NAMESCASESENSITIVE ON ;

SITE IOSite
  CLASS       PAD ;
  SYMMETRY    X Y R90 ;
  SIZE        0.010 BY 80.000 ;
END IOSite

SITE CornerSite
  CLASS       PAD ;
  SYMMETRY    X Y R90 ;
  SIZE        80.000 BY 80.000 ;
END CornerSite

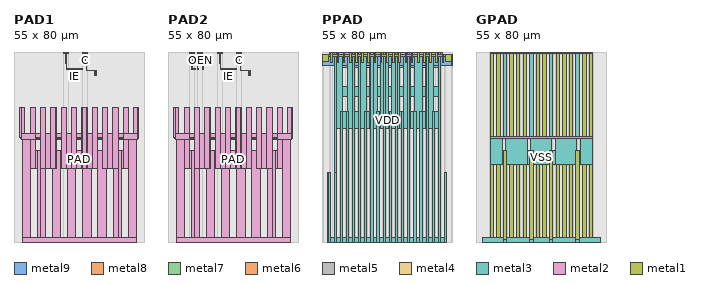
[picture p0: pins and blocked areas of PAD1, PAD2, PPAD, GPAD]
MACRO PAD1
  CLASS PAD ;
  ORIGIN 0 0 ;
  FOREIGN PAD1 0 0 ;
  SIZE 55 BY 80 ;
  SYMMETRY X Y R90 ;
  SITE IOSite ;
  PIN C
    DIRECTION OUTPUT ;
    USE SIGNAL ;
    PORT
      LAYER metal9 ;
        RECT 28.93 79.46 30.89 80 ;
      LAYER metal8 ;
        RECT 28.93 79.46 30.89 80 ;
      LAYER metal7 ;
        RECT 28.93 79.46 30.89 80 ;
      LAYER metal6 ;
        RECT 28.93 79.46 30.89 80 ;
      LAYER metal5 ;
        RECT 28.93 79.46 30.89 80 ;
      LAYER metal4 ;
        RECT 28.93 79.46 30.89 80 ;
      LAYER metal3 ;
        RECT 28.93 79.46 30.89 80 ;
      LAYER metal2 ;
        RECT 30.375 72.005 34.58 72.175 ;
        RECT 34.41 70.005 34.58 72.175 ;
        RECT 33.69 70.005 33.86 72.175 ;
        RECT 31.06 75.765 31.23 76.185 ;
        RECT 29.14 75.765 31.23 75.935 ;
        RECT 28.93 79.46 30.89 80 ;
        RECT 30.42 75.765 30.59 76.185 ;
        RECT 30.375 72.005 30.545 75.935 ;
        RECT 29.825 75.765 29.995 80 ;
        RECT 29.78 75.765 29.995 76.185 ;
        RECT 29.14 75.765 29.31 76.185 ;
      LAYER metal1 ;
        RECT 28.93 79.46 30.89 80 ;
    END
  AntennaGateArea 0.000 ;
  AntennaDiffArea 0.590 ;
  END C
  PIN IE
    DIRECTION INPUT ;
    USE SIGNAL ;
    PORT
      LAYER metal9 ;
        RECT 20.9 79.46 22.86 80 ;
      LAYER metal8 ;
        RECT 20.9 79.46 22.86 80 ;
      LAYER metal7 ;
        RECT 20.9 79.46 22.86 80 ;
      LAYER metal6 ;
        RECT 20.9 79.46 22.86 80 ;
      LAYER metal5 ;
        RECT 20.9 79.46 22.86 80 ;
      LAYER metal4 ;
        RECT 20.9 79.46 22.86 80 ;
      LAYER metal3 ;
        RECT 20.9 79.46 22.86 80 ;
      LAYER metal2 ;
        RECT 22.145 72.72 28.86 72.89 ;
        RECT 20.9 79.46 22.86 80 ;
        RECT 21.795 75.1 22.315 75.27 ;
        RECT 22.145 72.72 22.315 75.27 ;
        RECT 21.795 75.1 21.965 80 ;
      LAYER metal1 ;
        RECT 20.9 79.46 22.86 80 ;
    END
  AntennaGateArea 3.110 ;
  AntennaDiffArea 0.590 ;
  END IE
  PIN PAD
    DIRECTION INPUT ;
    USE SIGNAL ;
    PORT
      LAYER metal9 ;
        RECT 3.415 0 51.585 2 ;
      LAYER metal8 ;
        RECT 3.415 0 51.585 2 ;
      LAYER metal7 ;
        RECT 3.415 0 51.585 2 ;
      LAYER metal6 ;
        RECT 3.415 0 51.585 2 ;
      LAYER metal5 ;
        RECT 3.415 0 51.585 2 ;
      LAYER metal4 ;
        RECT 3.415 0 51.585 2 ;
      LAYER metal3 ;
        RECT 50.395 43.9 52.565 56.445 ;
        RECT 50.445 43.85 52.535 56.495 ;
        RECT 2.515 43.8 52.485 45.78 ;
        RECT 2.565 43.75 52.435 45.78 ;
        RECT 2.615 43.7 52.385 45.78 ;
        RECT 2.665 43.65 52.335 45.78 ;
        RECT 2.715 43.6 52.285 45.78 ;
        RECT 2.765 43.55 52.235 45.78 ;
        RECT 2.815 43.5 52.185 45.78 ;
        RECT 2.865 43.45 52.135 45.78 ;
        RECT 2.915 43.4 52.085 45.78 ;
        RECT 2.965 43.35 52.035 45.78 ;
        RECT 3.015 43.33 51.985 45.78 ;
        RECT 50.445 43.3 51.985 56.495 ;
        RECT 46.035 43.25 51.935 45.78 ;
        RECT 46.035 43.2 51.885 45.78 ;
        RECT 46.035 43.15 51.835 45.78 ;
        RECT 46.035 43.1 51.785 45.78 ;
        RECT 46.035 43.05 51.735 45.78 ;
        RECT 46.035 43 51.685 45.78 ;
        RECT 46.035 42.95 51.635 45.78 ;
        RECT 50.395 43.85 52.535 56.465 ;
        RECT 48.075 0 51.585 45.78 ;
        RECT 46.035 30.74 48.205 56.445 ;
        RECT 46.085 30.74 48.175 56.495 ;
        RECT 3.415 0 51.585 2 ;
        RECT 46.035 30.74 48.175 56.465 ;
        RECT 3.415 30.74 51.585 38.51 ;
        RECT 41.695 0 45.205 38.51 ;
        RECT 41.695 0 43.845 56.445 ;
        RECT 41.745 0 43.815 56.495 ;
        RECT 41.695 0 43.815 56.485 ;
        RECT 41.675 30.74 43.845 56.435 ;
        RECT 37.315 30.74 43.845 45.78 ;
        RECT 37.315 30.74 39.485 56.445 ;
        RECT 37.365 30.74 39.455 56.495 ;
        RECT 35.315 0 38.825 38.51 ;
        RECT 37.315 30.74 39.455 56.465 ;
        RECT 32.955 30.74 35.125 56.445 ;
        RECT 33.005 30.74 35.095 56.495 ;
        RECT 32.955 30.74 35.095 56.465 ;
        RECT 28.595 30.74 35.125 45.78 ;
        RECT 28.935 0 32.445 45.78 ;
        RECT 28.595 30.74 30.765 56.445 ;
        RECT 28.645 30.74 30.735 56.495 ;
        RECT 28.595 30.74 30.735 56.465 ;
        RECT 24.235 30.74 26.405 56.445 ;
        RECT 24.285 30.74 26.375 56.495 ;
        RECT 22.555 0 26.065 45.78 ;
        RECT 24.235 30.74 26.375 56.465 ;
        RECT 19.875 30.74 26.405 45.78 ;
        RECT 19.875 30.74 22.045 56.445 ;
        RECT 19.925 30.74 22.015 56.495 ;
        RECT 19.875 30.74 22.015 56.465 ;
        RECT 16.175 0 19.685 38.51 ;
        RECT 15.515 30.74 17.685 56.445 ;
        RECT 15.565 30.74 17.655 56.495 ;
        RECT 15.515 30.74 17.655 56.465 ;
        RECT 11.155 30.74 17.685 45.78 ;
        RECT 11.155 30.74 13.325 56.435 ;
        RECT 11.155 0 13.305 56.445 ;
        RECT 11.205 0 13.295 56.495 ;
        RECT 11.155 0 13.295 56.465 ;
        RECT 9.795 0 13.305 38.51 ;
        RECT 6.795 30.74 8.965 56.445 ;
        RECT 6.845 30.74 8.935 56.495 ;
        RECT 3.415 0 6.925 45.78 ;
        RECT 6.795 30.74 8.935 56.465 ;
        RECT 2.435 43.88 4.605 56.445 ;
        RECT 2.485 43.85 4.575 56.495 ;
        RECT 3.015 43.3 8.965 45.78 ;
        RECT 3.365 42.95 4.575 56.495 ;
        RECT 3.065 43.25 8.965 45.78 ;
        RECT 3.315 43 4.575 56.495 ;
        RECT 3.115 43.2 8.965 45.78 ;
        RECT 3.265 43.05 4.575 56.495 ;
        RECT 3.165 43.15 8.965 45.78 ;
        RECT 3.215 43.1 4.575 56.495 ;
        RECT 2.435 43.88 4.575 56.465 ;
      LAYER metal2 ;
        RECT 50.395 43.9 52.565 56.445 ;
        RECT 50.445 43.85 52.535 56.495 ;
        RECT 2.515 43.8 52.485 45.78 ;
        RECT 2.565 43.75 52.435 45.78 ;
        RECT 2.615 43.7 52.385 45.78 ;
        RECT 2.665 43.65 52.335 45.78 ;
        RECT 2.715 43.6 52.285 45.78 ;
        RECT 2.765 43.55 52.235 45.78 ;
        RECT 2.815 43.5 52.185 45.78 ;
        RECT 2.865 43.45 52.135 45.78 ;
        RECT 2.915 43.4 52.085 45.78 ;
        RECT 2.965 43.35 52.035 45.78 ;
        RECT 3.015 43.33 51.985 45.78 ;
        RECT 50.445 43.3 51.985 56.495 ;
        RECT 46.035 43.25 51.935 45.78 ;
        RECT 46.035 43.2 51.885 45.78 ;
        RECT 46.035 43.15 51.835 45.78 ;
        RECT 46.035 43.1 51.785 45.78 ;
        RECT 46.035 43.05 51.735 45.78 ;
        RECT 46.035 43 51.685 45.78 ;
        RECT 46.035 42.95 51.635 45.78 ;
        RECT 50.395 43.85 52.535 56.465 ;
        RECT 48.075 0 51.585 45.78 ;
        RECT 46.035 30.74 48.205 56.445 ;
        RECT 46.085 30.74 48.175 56.495 ;
        RECT 3.415 0 51.585 2 ;
        RECT 46.035 30.74 48.175 56.465 ;
        RECT 3.415 30.74 51.585 38.51 ;
        RECT 41.695 0 45.205 38.51 ;
        RECT 41.695 0 43.845 56.445 ;
        RECT 41.745 0 43.815 56.495 ;
        RECT 41.695 0 43.815 56.485 ;
        RECT 41.675 30.74 43.845 56.435 ;
        RECT 37.315 30.74 43.845 45.78 ;
        RECT 37.315 30.74 39.485 56.445 ;
        RECT 37.365 30.74 39.455 56.495 ;
        RECT 35.315 0 38.825 38.51 ;
        RECT 37.315 30.74 39.455 56.465 ;
        RECT 32.955 30.74 35.125 56.445 ;
        RECT 33.005 30.74 35.095 56.495 ;
        RECT 32.955 30.74 35.095 56.465 ;
        RECT 28.595 30.74 35.125 45.78 ;
        RECT 28.935 0 32.445 45.78 ;
        RECT 28.595 30.74 30.765 56.445 ;
        RECT 28.645 30.74 30.735 56.495 ;
        RECT 28.595 30.74 30.735 56.465 ;
        RECT 24.235 30.74 26.405 56.445 ;
        RECT 24.285 30.74 26.375 56.495 ;
        RECT 22.555 0 26.065 45.78 ;
        RECT 24.235 30.74 26.375 56.465 ;
        RECT 19.875 30.74 26.405 45.78 ;
        RECT 19.875 30.74 22.045 56.445 ;
        RECT 19.925 30.74 22.015 56.495 ;
        RECT 19.875 30.74 22.015 56.465 ;
        RECT 16.175 0 19.685 38.51 ;
        RECT 15.515 30.74 17.685 56.445 ;
        RECT 15.565 30.74 17.655 56.495 ;
        RECT 15.515 30.74 17.655 56.465 ;
        RECT 11.155 30.74 17.685 45.78 ;
        RECT 11.155 30.74 13.325 56.435 ;
        RECT 11.155 0 13.305 56.445 ;
        RECT 11.205 0 13.295 56.495 ;
        RECT 11.155 0 13.295 56.465 ;
        RECT 9.795 0 13.305 38.51 ;
        RECT 6.795 30.74 8.965 56.445 ;
        RECT 6.845 30.74 8.935 56.495 ;
        RECT 3.415 0 6.925 45.78 ;
        RECT 6.795 30.74 8.935 56.465 ;
        RECT 2.435 43.88 4.605 56.445 ;
        RECT 2.485 43.85 4.575 56.495 ;
        RECT 3.015 43.3 8.965 45.78 ;
        RECT 3.365 42.95 4.575 56.495 ;
        RECT 3.065 43.25 8.965 45.78 ;
        RECT 3.315 43 4.575 56.495 ;
        RECT 3.115 43.2 8.965 45.78 ;
        RECT 3.265 43.05 4.575 56.495 ;
        RECT 3.165 43.15 8.965 45.78 ;
        RECT 3.215 43.1 4.575 56.495 ;
        RECT 2.435 43.88 4.575 56.465 ;
    END
  END PAD
  OBS
    LAYER metal10 SPACING 0.4 ;
      RECT 0 0 55 80 ;
    LAYER via9 ;
      RECT 0 0 55 80 ;
    LAYER metal9 ;
      RECT 0 74.22 55 78.86 ;
      RECT 0 68.3 55 73.62 ;
      RECT 0 43.75 55 50.25 ;
      RECT 0 43.75 3 59.34 ;
      RECT 5.205 43.75 6.195 59.34 ;
      RECT 9.565 43.75 10.555 59.34 ;
      RECT 13.925 43.75 14.915 59.34 ;
      RECT 18.285 43.75 19.275 59.34 ;
      RECT 22.645 43.75 23.635 59.34 ;
      RECT 27.005 43.75 27.995 59.34 ;
      RECT 31.365 43.75 32.355 59.34 ;
      RECT 35.725 43.75 36.715 59.34 ;
      RECT 40.085 43.75 41.075 59.34 ;
      RECT 44.445 43.75 45.435 59.34 ;
      RECT 48.805 43.75 49.795 59.34 ;
      RECT 52 43.75 55 59.34 ;
      RECT 0 52.84 55 59.34 ;
      RECT 0 41.43 55 42.95 ;
      RECT 0 39.11 55 40.63 ;
      RECT 0 30.755 55 31.655 ;
      RECT 0 3.5 55 10.5 ;
      RECT 0 12.5 55 20.46 ;
      RECT 0 3.5 3 29.46 ;
      RECT 7.525 3.5 9.195 29.46 ;
      RECT 13.905 3.5 15.575 29.46 ;
      RECT 20.285 3.5 21.955 29.46 ;
      RECT 26.665 3.5 28.335 29.46 ;
      RECT 33.045 3.5 34.715 29.46 ;
      RECT 39.425 3.5 41.095 29.46 ;
      RECT 45.805 3.5 47.475 29.46 ;
      RECT 52 3.5 55 29.46 ;
      RECT 0 22.46 55 29.46 ;
    LAYER metal9 SPACING 0.4 ;
      RECT 0 0 2.785 80 ;
      RECT 0 2.63 55 78.86 ;
      RECT 0 2.63 20.27 80 ;
      RECT 23.49 2.63 28.3 80 ;
      RECT 52.215 0 55 80 ;
      RECT 31.52 2.63 55 80 ;
    LAYER via8 ;
      RECT 0 0 55 80 ;
    LAYER metal8 ;
      RECT 0 74.22 55 78.86 ;
      RECT 0 66.87 55 73.62 ;
      RECT 0 61.57 55 65.87 ;
      RECT 0 60.29 55 60.97 ;
      RECT 0 43.75 55 50.25 ;
      RECT 0 43.75 3 59.34 ;
      RECT 5.205 43.75 6.195 59.34 ;
      RECT 9.565 43.75 10.555 59.34 ;
      RECT 13.925 43.75 14.915 59.34 ;
      RECT 18.285 43.75 19.275 59.34 ;
      RECT 22.645 43.75 23.635 59.34 ;
      RECT 27.005 43.75 27.995 59.34 ;
      RECT 31.365 43.75 32.355 59.34 ;
      RECT 35.725 43.75 36.715 59.34 ;
      RECT 40.085 43.75 41.075 59.34 ;
      RECT 44.445 43.75 45.435 59.34 ;
      RECT 48.805 43.75 49.795 59.34 ;
      RECT 52 43.75 55 59.34 ;
      RECT 0 52.84 55 59.34 ;
      RECT 0 41.43 55 42.95 ;
      RECT 0 39.11 55 40.63 ;
      RECT 0 30.755 55 31.655 ;
      RECT 0 3.5 55 10.5 ;
      RECT 0 12.5 55 20.46 ;
      RECT 0 3.5 3 29.46 ;
      RECT 7.525 3.5 9.195 29.46 ;
      RECT 13.905 3.5 15.575 29.46 ;
      RECT 20.285 3.5 21.955 29.46 ;
      RECT 26.665 3.5 28.335 29.46 ;
      RECT 33.045 3.5 34.715 29.46 ;
      RECT 39.425 3.5 41.095 29.46 ;
      RECT 45.805 3.5 47.475 29.46 ;
      RECT 52 3.5 55 29.46 ;
      RECT 0 22.46 55 29.46 ;
    LAYER metal8 SPACING 0.1 ;
      RECT 0 0 3.085 80 ;
      RECT 0 2.33 55 79.13 ;
      RECT 0 2.33 20.57 80 ;
      RECT 23.19 2.33 28.6 80 ;
      RECT 51.915 0 55 80 ;
      RECT 31.22 2.33 55 80 ;
    LAYER via7 ;
      RECT 0 0 55 80 ;
    LAYER metal7 ;
      RECT 0 74.22 55 78.86 ;
      RECT 0 66.87 55 73.62 ;
      RECT 0 61.57 55 65.87 ;
      RECT 0 60.29 55 60.97 ;
      RECT 0 43.75 55 50.25 ;
      RECT 0 43.75 3 59.34 ;
      RECT 5.205 43.75 6.195 59.34 ;
      RECT 9.565 43.75 10.555 59.34 ;
      RECT 13.925 43.75 14.915 59.34 ;
      RECT 18.285 43.75 19.275 59.34 ;
      RECT 22.645 43.75 23.635 59.34 ;
      RECT 27.005 43.75 27.995 59.34 ;
      RECT 31.365 43.75 32.355 59.34 ;
      RECT 35.725 43.75 36.715 59.34 ;
      RECT 40.085 43.75 41.075 59.34 ;
      RECT 44.445 43.75 45.435 59.34 ;
      RECT 48.805 43.75 49.795 59.34 ;
      RECT 52 43.75 55 59.34 ;
      RECT 0 52.84 55 59.34 ;
      RECT 0 41.43 55 42.95 ;
      RECT 0 39.11 55 40.63 ;
      RECT 0 30.755 55 31.655 ;
      RECT 0 3.5 55 10.5 ;
      RECT 0 12.5 55 20.46 ;
      RECT 0 3.5 3 29.46 ;
      RECT 7.525 3.5 9.195 29.46 ;
      RECT 13.905 3.5 15.575 29.46 ;
      RECT 20.285 3.5 21.955 29.46 ;
      RECT 26.665 3.5 28.335 29.46 ;
      RECT 33.045 3.5 34.715 29.46 ;
      RECT 39.425 3.5 41.095 29.46 ;
      RECT 45.805 3.5 47.475 29.46 ;
      RECT 52 3.5 55 29.46 ;
      RECT 0 22.46 55 29.46 ;
    LAYER metal7 SPACING 0.1 ;
      RECT 0 0 3.24 80 ;
      RECT 0 2.175 55 79.285 ;
      RECT 0 2.175 20.725 80 ;
      RECT 23.035 2.175 28.755 80 ;
      RECT 51.76 0 55 80 ;
      RECT 31.065 2.175 55 80 ;
    LAYER via6 ;
      RECT 0 0 55 80 ;
    LAYER metal6 ;
      RECT 0 74.22 55 78.86 ;
      RECT 0 66.87 55 73.62 ;
      RECT 0 61.57 55 65.87 ;
      RECT 0 60.29 55 60.97 ;
      RECT 0 43.75 55 50.25 ;
      RECT 0 43.75 3 59.34 ;
      RECT 5.205 43.75 6.195 59.34 ;
      RECT 9.565 43.75 10.555 59.34 ;
      RECT 13.925 43.75 14.915 59.34 ;
      RECT 18.285 43.75 19.275 59.34 ;
      RECT 22.645 43.75 23.635 59.34 ;
      RECT 27.005 43.75 27.995 59.34 ;
      RECT 31.365 43.75 32.355 59.34 ;
      RECT 35.725 43.75 36.715 59.34 ;
      RECT 40.085 43.75 41.075 59.34 ;
      RECT 44.445 43.75 45.435 59.34 ;
      RECT 48.805 43.75 49.795 59.34 ;
      RECT 52 43.75 55 59.34 ;
      RECT 0 52.84 55 59.34 ;
      RECT 0 41.43 55 42.95 ;
      RECT 0 39.11 55 40.63 ;
      RECT 0 30.755 55 31.655 ;
      RECT 0 3.5 55 10.5 ;
      RECT 0 12.5 55 20.46 ;
      RECT 0 3.5 3 29.46 ;
      RECT 7.525 3.5 9.195 29.46 ;
      RECT 13.905 3.5 15.575 29.46 ;
      RECT 20.285 3.5 21.955 29.46 ;
      RECT 26.665 3.5 28.335 29.46 ;
      RECT 33.045 3.5 34.715 29.46 ;
      RECT 39.425 3.5 41.095 29.46 ;
      RECT 45.805 3.5 47.475 29.46 ;
      RECT 52 3.5 55 29.46 ;
      RECT 0 22.46 55 29.46 ;
    LAYER metal6 SPACING 0.1 ;
      RECT 0 0 3.24 80 ;
      RECT 0 2.175 55 79.285 ;
      RECT 0 2.175 20.725 80 ;
      RECT 23.035 2.175 28.755 80 ;
      RECT 51.76 0 55 80 ;
      RECT 31.065 2.175 55 80 ;
    LAYER via5 ;
      RECT 0 0 55 80 ;
    LAYER metal5 ;
      RECT 0 74.22 55 78.86 ;
      RECT 0 66.87 55 73.62 ;
      RECT 0 61.57 55 65.87 ;
      RECT 0 60.29 55 60.97 ;
      RECT 0 43.75 55 50.25 ;
      RECT 0 43.75 3 59.34 ;
      RECT 5.205 43.75 6.195 59.34 ;
      RECT 9.565 43.75 10.555 59.34 ;
      RECT 13.925 43.75 14.915 59.34 ;
      RECT 18.285 43.75 19.275 59.34 ;
      RECT 22.645 43.75 23.635 59.34 ;
      RECT 27.005 43.75 27.995 59.34 ;
      RECT 31.365 43.75 32.355 59.34 ;
      RECT 35.725 43.75 36.715 59.34 ;
      RECT 40.085 43.75 41.075 59.34 ;
      RECT 44.445 43.75 45.435 59.34 ;
      RECT 48.805 43.75 49.795 59.34 ;
      RECT 52 43.75 55 59.34 ;
      RECT 0 52.84 55 59.34 ;
      RECT 0 41.43 55 42.95 ;
      RECT 0 39.11 55 40.63 ;
      RECT 0 30.755 55 31.655 ;
      RECT 0 3.5 55 10.5 ;
      RECT 0 12.5 55 20.46 ;
      RECT 0 3.5 3 29.46 ;
      RECT 7.525 3.5 9.195 29.46 ;
      RECT 13.905 3.5 15.575 29.46 ;
      RECT 20.285 3.5 21.955 29.46 ;
      RECT 26.665 3.5 28.335 29.46 ;
      RECT 33.045 3.5 34.715 29.46 ;
      RECT 39.425 3.5 41.095 29.46 ;
      RECT 45.805 3.5 47.475 29.46 ;
      RECT 52 3.5 55 29.46 ;
      RECT 0 22.46 55 29.46 ;
    LAYER metal5 SPACING 0.1 ;
      RECT 0 0 3.24 80 ;
      RECT 0 2.175 55 79.285 ;
      RECT 0 2.175 20.725 80 ;
      RECT 23.035 2.175 28.755 80 ;
      RECT 51.76 0 55 80 ;
      RECT 31.065 2.175 55 80 ;
    LAYER via4 ;
      RECT 0 0 55 80 ;
    LAYER metal4 ;
      RECT 0 74.22 55 78.86 ;
      RECT 0 66.87 55 73.62 ;
      RECT 0 61.57 55 65.87 ;
      RECT 0 60.29 55 60.97 ;
      RECT 0 43.75 55 50.25 ;
      RECT 0 43.75 3 59.34 ;
      RECT 5.205 43.75 6.195 59.34 ;
      RECT 9.565 43.75 10.555 59.34 ;
      RECT 13.925 43.75 14.915 59.34 ;
      RECT 18.285 43.75 19.275 59.34 ;
      RECT 22.645 43.75 23.635 59.34 ;
      RECT 27.005 43.75 27.995 59.34 ;
      RECT 31.365 43.75 32.355 59.34 ;
      RECT 35.725 43.75 36.715 59.34 ;
      RECT 40.085 43.75 41.075 59.34 ;
      RECT 44.445 43.75 45.435 59.34 ;
      RECT 48.805 43.75 49.795 59.34 ;
      RECT 52 43.75 55 59.34 ;
      RECT 0 52.84 55 59.34 ;
      RECT 0 41.43 55 42.95 ;
      RECT 0 39.11 55 40.63 ;
      RECT 0 30.755 55 31.655 ;
      RECT 0 3.5 55 10.5 ;
      RECT 0 12.5 55 20.46 ;
      RECT 0 3.5 3 29.46 ;
      RECT 7.525 3.5 9.195 29.46 ;
      RECT 13.905 3.5 15.575 29.46 ;
      RECT 20.285 3.5 21.955 29.46 ;
      RECT 26.665 3.5 28.335 29.46 ;
      RECT 33.045 3.5 34.715 29.46 ;
      RECT 39.425 3.5 41.095 29.46 ;
      RECT 45.805 3.5 47.475 29.46 ;
      RECT 52 3.5 55 29.46 ;
      RECT 0 22.46 55 29.46 ;
    LAYER metal4 SPACING 0.1 ;
      RECT 0 0 3.24 80 ;
      RECT 0 2.175 55 79.285 ;
      RECT 0 2.175 20.725 80 ;
      RECT 23.035 2.175 28.755 80 ;
      RECT 51.76 0 55 80 ;
      RECT 31.065 2.175 55 80 ;
    LAYER via3 ;
      RECT 0 0 55 80 ;
    LAYER metal3 ;
      RECT 0 66.87 0.42 73.62 ;
      RECT 0 61.57 0.42 65.87 ;
      RECT 1.1 41.43 2.7 42.95 ;
      RECT 0 74.22 0.42 78.86 ;
      RECT 0 78.44 20.72 78.86 ;
      RECT 0.33 30.755 0.9 31.655 ;
      RECT 0.33 30.755 0.5 59.79 ;
      RECT 0.33 59.62 42.08 59.79 ;
      RECT 52.285 41.43 53.815 42.95 ;
      RECT 53.785 34.43 54.75 36.43 ;
      RECT 54.58 74.22 55 78.86 ;
      RECT 54.58 66.87 55 73.62 ;
      RECT 54.58 61.57 55 65.87 ;
    LAYER metal3 SPACING 0.1 ;
      RECT 7.1 2.175 9.62 30.565 ;
      RECT 9.14 38.685 10.98 43.155 ;
      RECT 13.48 2.175 16 30.565 ;
      RECT 17.86 38.685 19.7 43.155 ;
      RECT 19.86 2.175 22.38 30.565 ;
      RECT 26.58 38.685 28.42 43.155 ;
      RECT 26.24 2.175 28.76 30.565 ;
      RECT 32.62 2.175 35.14 30.565 ;
      RECT 35.3 38.685 37.14 43.155 ;
      RECT 39 2.175 41.52 30.565 ;
      RECT 44.02 38.685 45.86 43.155 ;
      RECT 45.38 2.175 47.9 30.565 ;
      RECT 0 0 3.24 42.775 ;
      RECT 51.76 0 55 42.775 ;
      RECT 0 0 3.19 42.825 ;
      RECT 51.81 0 55 42.825 ;
      RECT 0 0 3.14 42.875 ;
      RECT 51.86 0 55 42.875 ;
      RECT 0 0 3.09 42.925 ;
      RECT 51.91 0 55 42.925 ;
      RECT 0 0 3.04 42.975 ;
      RECT 51.96 0 55 42.975 ;
      RECT 0 0 2.99 43.025 ;
      RECT 52.01 0 55 43.025 ;
      RECT 0 0 2.94 43.075 ;
      RECT 52.06 0 55 43.075 ;
      RECT 0 0 2.89 43.125 ;
      RECT 52.11 0 55 43.125 ;
      RECT 0 0 2.84 43.175 ;
      RECT 52.16 0 55 43.175 ;
      RECT 0 0 2.79 43.225 ;
      RECT 52.21 0 55 43.225 ;
      RECT 0 0 2.74 43.275 ;
      RECT 52.26 0 55 43.275 ;
      RECT 0 0 2.69 43.325 ;
      RECT 52.31 0 55 43.325 ;
      RECT 0 0 2.64 43.375 ;
      RECT 52.36 0 55 43.375 ;
      RECT 0 0 2.59 43.425 ;
      RECT 52.41 0 55 43.425 ;
      RECT 0 0 2.54 43.475 ;
      RECT 52.46 0 55 43.475 ;
      RECT 0 0 2.49 43.525 ;
      RECT 52.51 0 55 43.525 ;
      RECT 0 0 2.44 43.575 ;
      RECT 52.56 0 55 43.575 ;
      RECT 0 0 2.39 43.625 ;
      RECT 52.61 0 55 43.625 ;
      RECT 0 0 2.34 43.675 ;
      RECT 52.66 0 55 43.675 ;
      RECT 0 0 2.31 43.705 ;
      RECT 52.71 0 55 43.725 ;
      RECT 39.66 45.955 41.5 80 ;
      RECT 13.48 56.61 15.34 80 ;
      RECT 22.22 45.955 24.06 79.285 ;
      RECT 0 0 2.26 80 ;
      RECT 4.78 45.955 6.62 80 ;
      RECT 4.75 56.62 6.62 80 ;
      RECT 9.14 45.955 10.98 80 ;
      RECT 9.11 56.62 10.98 80 ;
      RECT 13.5 45.955 15.34 80 ;
      RECT 13.47 56.62 15.34 80 ;
      RECT 17.86 45.955 19.7 80 ;
      RECT 17.83 56.62 19.7 80 ;
      RECT 22.19 56.62 24.06 79.285 ;
      RECT 26.58 45.955 28.42 80 ;
      RECT 26.55 56.62 28.42 80 ;
      RECT 30.91 56.62 32.78 79.285 ;
      RECT 35.3 45.955 37.14 80 ;
      RECT 35.27 56.62 37.14 80 ;
      RECT 44.02 45.955 45.86 80 ;
      RECT 43.99 56.62 45.86 80 ;
      RECT 48.38 45.955 50.22 80 ;
      RECT 48.35 56.62 50.22 80 ;
      RECT 39.66 56.61 41.52 80 ;
      RECT 39.63 56.62 41.52 80 ;
      RECT 0 56.64 2.31 80 ;
      RECT 4.75 56.64 6.67 80 ;
      RECT 9.11 56.64 11.03 80 ;
      RECT 13.47 56.64 15.39 80 ;
      RECT 17.83 56.64 19.75 80 ;
      RECT 22.19 56.64 24.11 79.285 ;
      RECT 26.55 56.64 28.47 80 ;
      RECT 30.91 56.64 32.83 79.285 ;
      RECT 35.27 56.64 37.19 80 ;
      RECT 39.63 56.66 41.57 80 ;
      RECT 43.99 56.64 45.91 80 ;
      RECT 48.35 56.64 50.27 80 ;
      RECT 52.71 56.62 55 80 ;
      RECT 30.94 45.955 32.78 79.285 ;
      RECT 0 56.67 55 79.285 ;
      RECT 0 56.67 20.725 80 ;
      RECT 23.035 56.67 28.755 80 ;
      RECT 52.74 0 55 80 ;
      RECT 31.065 56.67 55 80 ;
    LAYER via2 ;
      RECT 0 0 55 80 ;
    LAYER metal2 ;
      RECT 0 66.87 0.42 73.62 ;
      RECT 0 61.57 0.42 65.87 ;
      RECT 1.1 41.43 2.7 42.95 ;
      RECT 0 74.22 0.42 78.86 ;
      RECT 0 78.44 20.72 78.86 ;
      RECT 22.175 75.5 22.345 77.27 ;
      RECT 28.7 71.845 28.87 72.415 ;
      RECT 29.385 71.915 29.555 72.285 ;
      RECT 29.745 71.93 29.915 72.3 ;
      RECT 29.67 72.13 29.84 74.215 ;
      RECT 23.225 74.045 29.84 74.215 ;
      RECT 23.225 74.045 23.395 76.7 ;
      RECT 29.98 73.73 30.15 74.1 ;
      RECT 29.77 64.64 29.94 65.93 ;
      RECT 28.39 65.76 29.94 65.93 ;
      RECT 28.39 65.76 28.56 70.83 ;
      RECT 28.39 70.66 30.22 70.83 ;
      RECT 29.06 70.66 29.23 73.925 ;
      RECT 22.495 73.755 29.23 73.925 ;
      RECT 22.495 73.755 22.665 77.27 ;
      RECT 35.12 70.005 35.29 72.51 ;
      RECT 34.615 72.34 35.29 72.51 ;
      RECT 34.615 72.34 34.785 72.89 ;
      RECT 30.8 72.72 34.785 72.89 ;
      RECT 30.8 72.72 30.97 75.27 ;
      RECT 30.77 75.1 31.65 75.27 ;
      RECT 31.48 75.1 31.65 75.935 ;
      RECT 31.48 75.765 33.15 75.935 ;
      RECT 31.7 75.765 31.87 76.185 ;
      RECT 32.34 75.765 32.51 76.185 ;
      RECT 32.98 75.765 33.15 76.185 ;
      RECT 36.2 70.005 36.37 72.175 ;
      RECT 35.62 72.005 36.37 72.175 ;
      RECT 35.62 72.005 35.79 72.89 ;
      RECT 34.935 72.72 35.79 72.89 ;
      RECT 35.07 72.72 35.24 75.27 ;
      RECT 33.01 75.1 35.24 75.27 ;
      RECT 34.47 75.1 34.64 76.15 ;
      RECT 52.285 41.43 53.815 42.95 ;
      RECT 54.58 34.43 54.75 59.32 ;
      RECT 48.725 59.15 54.75 59.32 ;
      RECT 44.465 63.09 48.895 63.26 ;
      RECT 44.465 63.09 44.635 64.06 ;
      RECT 45.885 63.09 46.055 64.06 ;
      RECT 47.305 63.09 47.475 64.06 ;
      RECT 48.725 59.15 48.895 64.06 ;
      RECT 54.58 74.22 55 78.86 ;
      RECT 54.58 66.87 55 73.62 ;
      RECT 54.58 61.57 55 65.87 ;
    LAYER metal2 SPACING 0.1 ;
      RECT 7.1 2.175 9.62 30.565 ;
      RECT 9.14 38.685 10.98 43.155 ;
      RECT 13.48 2.175 16 30.565 ;
      RECT 17.86 38.685 19.7 43.155 ;
      RECT 19.86 2.175 22.38 30.565 ;
      RECT 26.58 38.685 28.42 43.155 ;
      RECT 26.24 2.175 28.76 30.565 ;
      RECT 32.62 2.175 35.14 30.565 ;
      RECT 35.3 38.685 37.14 43.155 ;
      RECT 39 2.175 41.52 30.565 ;
      RECT 44.02 38.685 45.86 43.155 ;
      RECT 45.38 2.175 47.9 30.565 ;
      RECT 0 0 3.24 42.775 ;
      RECT 51.76 0 55 42.775 ;
      RECT 0 0 3.19 42.825 ;
      RECT 51.81 0 55 42.825 ;
      RECT 0 0 3.14 42.875 ;
      RECT 51.86 0 55 42.875 ;
      RECT 0 0 3.09 42.925 ;
      RECT 51.91 0 55 42.925 ;
      RECT 0 0 3.04 42.975 ;
      RECT 51.96 0 55 42.975 ;
      RECT 0 0 2.99 43.025 ;
      RECT 52.01 0 55 43.025 ;
      RECT 0 0 2.94 43.075 ;
      RECT 52.06 0 55 43.075 ;
      RECT 0 0 2.89 43.125 ;
      RECT 52.11 0 55 43.125 ;
      RECT 0 0 2.84 43.175 ;
      RECT 52.16 0 55 43.175 ;
      RECT 0 0 2.79 43.225 ;
      RECT 52.21 0 55 43.225 ;
      RECT 0 0 2.74 43.275 ;
      RECT 52.26 0 55 43.275 ;
      RECT 0 0 2.69 43.325 ;
      RECT 52.31 0 55 43.325 ;
      RECT 0 0 2.64 43.375 ;
      RECT 52.36 0 55 43.375 ;
      RECT 0 0 2.59 43.425 ;
      RECT 52.41 0 55 43.425 ;
      RECT 0 0 2.54 43.475 ;
      RECT 52.46 0 55 43.475 ;
      RECT 0 0 2.49 43.525 ;
      RECT 52.51 0 55 43.525 ;
      RECT 0 0 2.44 43.575 ;
      RECT 52.56 0 55 43.575 ;
      RECT 0 0 2.39 43.625 ;
      RECT 52.61 0 55 43.625 ;
      RECT 0 0 2.34 43.675 ;
      RECT 52.66 0 55 43.675 ;
      RECT 0 0 2.31 43.705 ;
      RECT 52.71 0 55 43.725 ;
      RECT 39.66 45.955 41.5 80 ;
      RECT 13.48 56.61 15.34 80 ;
      RECT 0 0 2.26 80 ;
      RECT 4.78 45.955 6.62 80 ;
      RECT 4.75 56.62 6.62 80 ;
      RECT 9.14 45.955 10.98 80 ;
      RECT 9.11 56.62 10.98 80 ;
      RECT 13.5 45.955 15.34 80 ;
      RECT 13.47 56.62 15.34 80 ;
      RECT 17.86 45.955 19.7 80 ;
      RECT 17.83 56.62 19.7 80 ;
      RECT 22.22 45.955 24.06 72.545 ;
      RECT 22.19 56.62 24.06 72.545 ;
      RECT 26.58 45.955 28.42 72.545 ;
      RECT 26.55 56.62 28.42 72.545 ;
      RECT 30.94 45.955 32.78 71.83 ;
      RECT 30.91 56.62 32.78 71.83 ;
      RECT 35.3 45.955 37.14 80 ;
      RECT 35.27 56.62 37.14 80 ;
      RECT 44.02 45.955 45.86 80 ;
      RECT 43.99 56.62 45.86 80 ;
      RECT 48.38 45.955 50.22 80 ;
      RECT 48.35 56.62 50.22 80 ;
      RECT 39.66 56.61 41.52 80 ;
      RECT 39.63 56.62 41.52 80 ;
      RECT 0 56.64 2.31 80 ;
      RECT 4.75 56.64 6.67 80 ;
      RECT 9.11 56.64 11.03 80 ;
      RECT 13.47 56.64 15.39 80 ;
      RECT 17.83 56.64 19.75 80 ;
      RECT 22.19 56.64 24.11 72.545 ;
      RECT 26.55 56.64 28.47 72.545 ;
      RECT 30.91 56.64 32.83 71.83 ;
      RECT 35.27 56.64 37.19 80 ;
      RECT 39.63 56.66 41.57 80 ;
      RECT 43.99 56.64 45.91 80 ;
      RECT 48.35 56.64 50.27 80 ;
      RECT 0 56.67 55 69.83 ;
      RECT 0 56.67 33.515 71.83 ;
      RECT 34.035 56.67 34.235 71.83 ;
      RECT 34.755 56.67 55 80 ;
      RECT 34.615 72.34 55 80 ;
      RECT 0 56.67 30.2 72.545 ;
      RECT 0 56.67 21.97 74.925 ;
      RECT 22.49 73.065 30.2 75.59 ;
      RECT 29.035 56.67 30.2 75.59 ;
      RECT 30.72 72.35 55 75.59 ;
      RECT 22.14 75.445 28.965 79.285 ;
      RECT 29.485 76.11 29.605 79.285 ;
      RECT 30.765 76.11 30.885 79.285 ;
      RECT 52.71 56.62 55 80 ;
      RECT 31.405 72.35 55 80 ;
      RECT 0 56.67 21.62 79.285 ;
      RECT 22.14 76.36 29.65 79.285 ;
      RECT 30.17 76.36 55 79.285 ;
      RECT 0 56.67 20.725 80 ;
      RECT 23.035 73.065 28.755 80 ;
      RECT 52.74 0 55 80 ;
      RECT 31.065 76.36 55 80 ;
    LAYER via1 ;
      RECT 0 0 55 80 ;
    LAYER metal1 ;
      RECT 0 74.22 55 74.64 ;
      RECT 24.315 74.22 24.715 75.02 ;
      RECT 25.475 74.22 25.875 75.02 ;
      RECT 26.635 74.22 27.035 75.02 ;
      RECT 44.935 74.22 45.335 75.02 ;
      RECT 46.095 74.22 46.495 75.02 ;
      RECT 47.255 74.22 47.655 75.02 ;
      RECT 48.415 74.22 48.815 75.02 ;
      RECT 49.575 74.22 49.975 75.02 ;
      RECT 50.735 74.22 51.135 75.02 ;
      RECT 51.895 74.22 52.295 75.02 ;
      RECT 53.055 74.22 53.455 75.02 ;
      RECT 1.115 74.22 1.515 75.04 ;
      RECT 2.275 74.22 2.675 75.04 ;
      RECT 3.435 74.22 3.835 75.04 ;
      RECT 4.595 74.22 4.995 75.04 ;
      RECT 5.755 74.22 6.155 75.04 ;
      RECT 6.915 74.22 7.315 75.04 ;
      RECT 8.075 74.22 8.475 75.04 ;
      RECT 9.235 74.22 9.635 75.04 ;
      RECT 10.395 74.22 10.795 75.04 ;
      RECT 11.555 74.22 11.955 75.04 ;
      RECT 12.715 74.22 13.115 75.04 ;
      RECT 13.875 74.22 14.275 75.04 ;
      RECT 15.035 74.22 15.435 75.04 ;
      RECT 16.195 74.22 16.595 75.04 ;
      RECT 17.355 74.22 17.755 75.04 ;
      RECT 18.515 74.22 18.915 75.04 ;
      RECT 19.675 74.22 20.075 75.04 ;
      RECT 42.19 75.73 42.36 77.05 ;
      RECT 0 74.22 0.42 78.86 ;
      RECT 1.115 78.04 1.515 78.86 ;
      RECT 2.275 78.04 2.675 78.86 ;
      RECT 3.435 78.04 3.835 78.86 ;
      RECT 4.595 78.04 4.995 78.86 ;
      RECT 5.755 78.04 6.155 78.86 ;
      RECT 6.915 78.04 7.315 78.86 ;
      RECT 8.075 78.04 8.475 78.86 ;
      RECT 9.235 78.04 9.635 78.86 ;
      RECT 10.395 78.04 10.795 78.86 ;
      RECT 11.555 78.04 11.955 78.86 ;
      RECT 12.715 78.04 13.115 78.86 ;
      RECT 13.875 78.04 14.275 78.86 ;
      RECT 15.035 78.04 15.435 78.86 ;
      RECT 16.195 78.04 16.595 78.86 ;
      RECT 17.355 78.04 17.755 78.86 ;
      RECT 18.515 78.04 18.915 78.86 ;
      RECT 19.675 78.04 20.075 78.86 ;
      RECT 20.92 74.22 21.42 78.86 ;
      RECT 22.175 75.5 22.345 78.86 ;
      RECT 22.905 75.73 23.075 78.86 ;
      RECT 24.315 78.02 24.715 78.86 ;
      RECT 25.475 78.02 25.875 78.86 ;
      RECT 26.635 78.02 27.035 78.86 ;
      RECT 27.855 74.22 28.355 78.86 ;
      RECT 28.82 75.73 28.99 78.86 ;
      RECT 29.46 75.73 29.63 78.86 ;
      RECT 30.1 75.73 30.27 78.86 ;
      RECT 30.74 75.73 30.91 78.86 ;
      RECT 31.38 75.73 31.55 78.86 ;
      RECT 32.02 75.73 32.19 78.86 ;
      RECT 32.66 75.73 32.83 78.86 ;
      RECT 33.3 75.73 33.47 78.86 ;
      RECT 34.15 75.71 34.32 78.86 ;
      RECT 34.79 75.71 34.96 78.86 ;
      RECT 36.615 75.635 36.785 78.86 ;
      RECT 38.035 75.635 38.205 78.86 ;
      RECT 39.455 75.635 39.625 78.86 ;
      RECT 40.77 75.73 40.94 78.86 ;
      RECT 42.23 75.915 42.4 78.86 ;
      RECT 43.685 74.22 43.935 78.86 ;
      RECT 44.935 78.02 45.335 78.86 ;
      RECT 46.095 78.02 46.495 78.86 ;
      RECT 47.255 78.02 47.655 78.86 ;
      RECT 48.415 78.02 48.815 78.86 ;
      RECT 49.575 78.02 49.975 78.86 ;
      RECT 50.735 78.02 51.135 78.86 ;
      RECT 51.895 78.02 52.295 78.86 ;
      RECT 53.055 78.02 53.455 78.86 ;
      RECT 54.58 74.22 55 78.86 ;
      RECT 0 78.44 55 78.86 ;
      RECT 0 66.87 55 67.29 ;
      RECT 1.115 66.87 1.515 67.775 ;
      RECT 2.275 66.87 2.675 67.775 ;
      RECT 3.435 66.87 3.835 67.775 ;
      RECT 4.595 66.87 4.995 67.775 ;
      RECT 5.755 66.87 6.155 67.775 ;
      RECT 6.915 66.87 7.315 67.775 ;
      RECT 8.075 66.87 8.475 67.775 ;
      RECT 9.235 66.87 9.635 67.775 ;
      RECT 10.395 66.87 10.795 67.775 ;
      RECT 11.555 66.87 11.955 67.775 ;
      RECT 12.715 66.87 13.115 67.775 ;
      RECT 13.875 66.87 14.275 67.775 ;
      RECT 15.035 66.87 15.435 67.775 ;
      RECT 16.195 66.87 16.595 67.775 ;
      RECT 17.355 66.87 17.755 67.775 ;
      RECT 18.515 66.87 18.915 67.775 ;
      RECT 19.675 66.87 20.075 67.775 ;
      RECT 20.835 66.87 21.235 67.775 ;
      RECT 21.995 66.87 22.395 67.775 ;
      RECT 23.155 66.87 23.555 67.775 ;
      RECT 24.315 66.87 24.715 67.775 ;
      RECT 25.475 66.87 25.875 67.775 ;
      RECT 28.7 66.87 28.87 70.295 ;
      RECT 30.4 66.87 30.57 70.295 ;
      RECT 32.1 66.87 32.27 70.295 ;
      RECT 27.14 66.87 27.31 71.385 ;
      RECT 33.33 66.87 33.5 72.295 ;
      RECT 34.05 66.87 34.22 72.295 ;
      RECT 34.76 66.87 34.93 72.295 ;
      RECT 35.84 66.87 36.01 72.295 ;
      RECT 36.56 66.87 36.73 72.295 ;
      RECT 0 66.87 0.42 73.62 ;
      RECT 1.115 72.85 1.515 73.62 ;
      RECT 2.275 72.85 2.675 73.62 ;
      RECT 3.435 72.85 3.835 73.62 ;
      RECT 4.595 72.85 4.995 73.62 ;
      RECT 5.755 72.85 6.155 73.62 ;
      RECT 6.915 72.85 7.315 73.62 ;
      RECT 8.075 72.85 8.475 73.62 ;
      RECT 9.235 72.85 9.635 73.62 ;
      RECT 10.395 72.85 10.795 73.62 ;
      RECT 11.555 72.85 11.955 73.62 ;
      RECT 12.715 72.85 13.115 73.62 ;
      RECT 13.875 72.85 14.275 73.62 ;
      RECT 15.035 72.85 15.435 73.62 ;
      RECT 16.195 72.85 16.595 73.62 ;
      RECT 17.355 72.85 17.755 73.62 ;
      RECT 18.515 72.85 18.915 73.62 ;
      RECT 19.675 72.85 20.075 73.62 ;
      RECT 20.835 72.85 21.235 73.62 ;
      RECT 21.995 72.85 22.395 73.62 ;
      RECT 23.155 72.85 23.555 73.62 ;
      RECT 24.315 72.85 24.715 73.62 ;
      RECT 25.475 72.85 25.875 73.62 ;
      RECT 52.44 71.34 52.61 73.62 ;
      RECT 54.695 66.87 55 73.62 ;
      RECT 0 73.2 55 73.62 ;
      RECT 0 61.57 55 61.99 ;
      RECT 1.115 61.57 1.515 62.34 ;
      RECT 2.275 61.57 2.675 62.34 ;
      RECT 3.435 61.57 3.835 62.34 ;
      RECT 4.595 61.57 4.995 62.34 ;
      RECT 5.755 61.57 6.155 62.34 ;
      RECT 6.915 61.57 7.315 62.34 ;
      RECT 8.075 61.57 8.475 62.34 ;
      RECT 9.235 61.57 9.635 62.34 ;
      RECT 10.395 61.57 10.795 62.34 ;
      RECT 11.555 61.57 11.955 62.34 ;
      RECT 12.715 61.57 13.115 62.34 ;
      RECT 13.875 61.57 14.275 62.34 ;
      RECT 15.035 61.57 15.435 62.34 ;
      RECT 16.195 61.57 16.595 62.34 ;
      RECT 17.355 61.57 17.755 62.34 ;
      RECT 18.515 61.57 18.915 62.34 ;
      RECT 19.675 61.57 20.075 62.34 ;
      RECT 20.835 61.57 21.235 62.34 ;
      RECT 21.995 61.57 22.395 62.34 ;
      RECT 23.155 61.57 23.555 62.34 ;
      RECT 24.315 61.57 24.715 62.34 ;
      RECT 25.475 61.57 25.875 62.34 ;
      RECT 30.835 61.57 31.005 64.22 ;
      RECT 36.545 61.57 36.715 64.41 ;
      RECT 50.73 61.57 50.9 64.41 ;
      RECT 52.15 61.57 52.32 64.41 ;
      RECT 37.665 61.57 37.835 64.43 ;
      RECT 39.085 61.57 39.255 64.43 ;
      RECT 40.505 61.57 40.675 64.505 ;
      RECT 0 61.57 0.42 65.87 ;
      RECT 1.115 65.1 1.515 65.87 ;
      RECT 2.275 65.1 2.675 65.87 ;
      RECT 3.435 65.1 3.835 65.87 ;
      RECT 4.595 65.1 4.995 65.87 ;
      RECT 5.755 65.1 6.155 65.87 ;
      RECT 6.915 65.1 7.315 65.87 ;
      RECT 8.075 65.1 8.475 65.87 ;
      RECT 9.235 65.1 9.635 65.87 ;
      RECT 10.395 65.1 10.795 65.87 ;
      RECT 11.555 65.1 11.955 65.87 ;
      RECT 12.715 65.1 13.115 65.87 ;
      RECT 13.875 65.1 14.275 65.87 ;
      RECT 15.035 65.1 15.435 65.87 ;
      RECT 16.195 65.1 16.595 65.87 ;
      RECT 17.355 65.1 17.755 65.87 ;
      RECT 18.515 65.1 18.915 65.87 ;
      RECT 19.675 65.1 20.075 65.87 ;
      RECT 20.835 65.1 21.235 65.87 ;
      RECT 21.995 65.1 22.395 65.87 ;
      RECT 23.155 65.1 23.555 65.87 ;
      RECT 24.315 65.1 24.715 65.87 ;
      RECT 25.475 65.1 25.875 65.87 ;
      RECT 26.92 61.57 27.42 65.87 ;
      RECT 28.29 64.04 28.46 65.87 ;
      RECT 54.58 61.57 55 65.87 ;
      RECT 0 65.45 55 65.87 ;
      RECT 0 60.29 55 60.97 ;
      RECT 0 43.75 55 45.065 ;
      RECT 0 46.53 1.835 56.445 ;
      RECT 53.165 46.51 55 56.465 ;
      RECT 0 46.48 1.805 56.495 ;
      RECT 53.215 46.48 55 56.495 ;
      RECT 0 43.75 0.5 59.34 ;
      RECT 54.5 43.75 55 59.34 ;
      RECT 0 57.97 55 59.34 ;
      RECT 0 41.43 55 42.95 ;
      RECT 0 39.11 55 40.63 ;
      RECT 0 0 55 0.4 ;
      RECT 0 3.85 2.815 27.95 ;
      RECT 52.185 3.85 55 27.95 ;
      RECT 0 3.8 2.765 28 ;
      RECT 52.235 3.8 55 28 ;
      RECT 0 3.75 2.715 28.05 ;
      RECT 52.285 3.75 55 28.05 ;
      RECT 0 3.7 2.665 28.1 ;
      RECT 52.335 3.7 55 28.1 ;
      RECT 0 3.65 2.615 28.15 ;
      RECT 52.385 3.65 55 28.15 ;
      RECT 0 3.6 2.565 28.2 ;
      RECT 52.435 3.6 55 28.2 ;
      RECT 0 0 1.185 33.47 ;
      RECT 53.815 0 55 32.93 ;
      RECT 0 32.55 55 32.93 ;
      RECT 0 32.55 40.715 33.47 ;
      RECT 0 0 0.75 38.31 ;
      RECT 2.025 35.53 40.715 38.31 ;
      RECT 6.15 32.55 40.715 38.31 ;
      RECT 0 36.04 40.715 38.31 ;
      RECT 54.6 0 55 38.31 ;
      RECT 0 37.93 55 38.31 ;
    LAYER metal1 SPACING 0.09 ;
      RECT 0 0 55 79.295 ;
      RECT 0 0 20.735 80 ;
      RECT 23.025 0 28.765 80 ;
      RECT 31.055 0 55 80 ;
  END
END PAD1
MACRO PAD2
  CLASS PAD ;
  ORIGIN 0 0 ;
  FOREIGN PAD2 0 0 ;
  SIZE 55 BY 80 ;
  SYMMETRY X Y R90 ;
  SITE IOSite ;
  PIN C
    DIRECTION OUTPUT ;
    USE SIGNAL ;
    PORT
      LAYER metal9 ;
        RECT 28.93 79.46 30.89 80 ;
      LAYER metal8 ;
        RECT 28.93 79.46 30.89 80 ;
      LAYER metal7 ;
        RECT 28.93 79.46 30.89 80 ;
      LAYER metal6 ;
        RECT 28.93 79.46 30.89 80 ;
      LAYER metal5 ;
        RECT 28.93 79.46 30.89 80 ;
      LAYER metal4 ;
        RECT 28.93 79.46 30.89 80 ;
      LAYER metal3 ;
        RECT 28.93 79.46 30.89 80 ;
      LAYER metal2 ;
        RECT 30.375 72.005 34.58 72.175 ;
        RECT 34.41 70.005 34.58 72.175 ;
        RECT 33.69 70.005 33.86 72.175 ;
        RECT 31.06 75.765 31.23 76.185 ;
        RECT 29.14 75.765 31.23 75.935 ;
        RECT 28.93 79.46 30.89 80 ;
        RECT 30.42 75.765 30.59 76.185 ;
        RECT 30.375 72.005 30.545 75.935 ;
        RECT 29.825 75.765 29.995 80 ;
        RECT 29.78 75.765 29.995 76.185 ;
        RECT 29.14 75.765 29.31 76.185 ;
      LAYER metal1 ;
        RECT 28.93 79.46 30.89 80 ;
    END
  AntennaGateArea 0.000 ;
  AntennaDiffArea 0.590 ;
  END C
  PIN I
    DIRECTION INPUT ;
    USE SIGNAL ;
    PORT
      LAYER metal9 ;
        RECT 9.105 79.46 11.065 80 ;
      LAYER metal8 ;
        RECT 9.105 79.46 11.065 80 ;
      LAYER metal7 ;
        RECT 9.105 79.46 11.065 80 ;
      LAYER metal6 ;
        RECT 9.105 79.46 11.065 80 ;
      LAYER metal5 ;
        RECT 9.105 79.46 11.065 80 ;
      LAYER metal4 ;
        RECT 9.105 79.46 11.065 80 ;
      LAYER metal3 ;
        RECT 10 75.1 15.445 75.27 ;
        RECT 10 72.72 11.53 72.89 ;
        RECT 9.105 79.46 11.065 80 ;
        RECT 10 72.72 10.17 80 ;
      LAYER metal2 ;
        RECT 9.105 79.46 11.065 80 ;
      LAYER metal1 ;
        RECT 9.105 79.46 11.065 80 ;
    END
  AntennaGateArea 0.700 ;
  AntennaDiffArea 0.590 ;
  END I
  PIN IE
    DIRECTION INPUT ;
    USE SIGNAL ;
    PORT
      LAYER metal9 ;
        RECT 20.9 79.46 22.86 80 ;
      LAYER metal8 ;
        RECT 20.9 79.46 22.86 80 ;
      LAYER metal7 ;
        RECT 20.9 79.46 22.86 80 ;
      LAYER metal6 ;
        RECT 20.9 79.46 22.86 80 ;
      LAYER metal5 ;
        RECT 20.9 79.46 22.86 80 ;
      LAYER metal4 ;
        RECT 20.9 79.46 22.86 80 ;
      LAYER metal3 ;
        RECT 20.9 79.46 22.86 80 ;
      LAYER metal2 ;
        RECT 22.145 72.72 28.86 72.89 ;
        RECT 20.9 79.46 22.86 80 ;
        RECT 21.795 75.1 22.315 75.27 ;
        RECT 22.145 72.72 22.315 75.27 ;
        RECT 21.795 75.1 21.965 80 ;
      LAYER metal1 ;
        RECT 20.9 79.46 22.86 80 ;
    END
  AntennaGateArea 3.110 ;
  AntennaDiffArea 0.590 ;
  END IE
  PIN OEN
    DIRECTION INPUT ;
    USE SIGNAL ;
    PORT
      LAYER metal9 ;
        RECT 12.495 79.46 14.455 80 ;
      LAYER metal8 ;
        RECT 12.495 79.46 14.455 80 ;
      LAYER metal7 ;
        RECT 12.495 79.46 14.455 80 ;
      LAYER metal6 ;
        RECT 12.495 79.46 14.455 80 ;
      LAYER metal5 ;
        RECT 12.495 79.46 14.455 80 ;
      LAYER metal4 ;
        RECT 12.495 79.46 14.455 80 ;
      LAYER metal3 ;
        RECT 12.495 79.46 14.455 80 ;
      LAYER metal2 ;
        RECT 12.43 75.1 14.835 75.27 ;
        RECT 14.625 72.72 14.795 75.27 ;
        RECT 14.425 72.72 14.795 72.89 ;
        RECT 12.495 79.46 14.455 80 ;
        RECT 13.39 75.1 13.56 80 ;
        RECT 12.43 72.72 12.8 72.89 ;
        RECT 12.43 72.72 12.6 75.27 ;
      LAYER metal1 ;
        RECT 12.495 79.46 14.455 80 ;
    END
  AntennaGateArea 0.560 ;
  AntennaDiffArea 0.590 ;
  END OEN
  PIN PAD
    DIRECTION INOUT ;
    USE SIGNAL ;
    PORT
      LAYER metal9 ;
        RECT 3.415 0 51.585 2 ;
      LAYER metal8 ;
        RECT 3.415 0 51.585 2 ;
      LAYER metal7 ;
        RECT 3.415 0 51.585 2 ;
      LAYER metal6 ;
        RECT 3.415 0 51.585 2 ;
      LAYER metal5 ;
        RECT 3.415 0 51.585 2 ;
      LAYER metal4 ;
        RECT 3.415 0 51.585 2 ;
      LAYER metal3 ;
        RECT 50.395 43.9 52.565 56.445 ;
        RECT 50.445 43.85 52.535 56.495 ;
        RECT 2.515 43.8 52.485 45.78 ;
        RECT 2.565 43.75 52.435 45.78 ;
        RECT 2.615 43.7 52.385 45.78 ;
        RECT 2.665 43.65 52.335 45.78 ;
        RECT 2.715 43.6 52.285 45.78 ;
        RECT 2.765 43.55 52.235 45.78 ;
        RECT 2.815 43.5 52.185 45.78 ;
        RECT 2.865 43.45 52.135 45.78 ;
        RECT 2.915 43.4 52.085 45.78 ;
        RECT 2.965 43.35 52.035 45.78 ;
        RECT 3.015 43.33 51.985 45.78 ;
        RECT 50.445 43.3 51.985 56.495 ;
        RECT 46.035 43.25 51.935 45.78 ;
        RECT 46.035 43.2 51.885 45.78 ;
        RECT 46.035 43.15 51.835 45.78 ;
        RECT 46.035 43.1 51.785 45.78 ;
        RECT 46.035 43.05 51.735 45.78 ;
        RECT 46.035 43 51.685 45.78 ;
        RECT 46.035 42.95 51.635 45.78 ;
        RECT 50.395 43.85 52.535 56.465 ;
        RECT 48.075 0 51.585 45.78 ;
        RECT 46.035 30.74 48.205 56.445 ;
        RECT 46.085 30.74 48.175 56.495 ;
        RECT 3.415 0 51.585 2 ;
        RECT 46.035 30.74 48.175 56.465 ;
        RECT 3.415 30.74 51.585 38.51 ;
        RECT 41.695 0 45.205 38.51 ;
        RECT 41.695 0 43.845 56.445 ;
        RECT 41.745 0 43.815 56.495 ;
        RECT 41.695 0 43.815 56.485 ;
        RECT 41.675 30.74 43.845 56.435 ;
        RECT 37.315 30.74 43.845 45.78 ;
        RECT 37.315 30.74 39.485 56.445 ;
        RECT 37.365 30.74 39.455 56.495 ;
        RECT 35.315 0 38.825 38.51 ;
        RECT 37.315 30.74 39.455 56.465 ;
        RECT 32.955 30.74 35.125 56.445 ;
        RECT 33.005 30.74 35.095 56.495 ;
        RECT 32.955 30.74 35.095 56.465 ;
        RECT 28.595 30.74 35.125 45.78 ;
        RECT 28.935 0 32.445 45.78 ;
        RECT 28.595 30.74 30.765 56.445 ;
        RECT 28.645 30.74 30.735 56.495 ;
        RECT 28.595 30.74 30.735 56.465 ;
        RECT 24.235 30.74 26.405 56.445 ;
        RECT 24.285 30.74 26.375 56.495 ;
        RECT 22.555 0 26.065 45.78 ;
        RECT 24.235 30.74 26.375 56.465 ;
        RECT 19.875 30.74 26.405 45.78 ;
        RECT 19.875 30.74 22.045 56.445 ;
        RECT 19.925 30.74 22.015 56.495 ;
        RECT 19.875 30.74 22.015 56.465 ;
        RECT 16.175 0 19.685 38.51 ;
        RECT 15.515 30.74 17.685 56.445 ;
        RECT 15.565 30.74 17.655 56.495 ;
        RECT 15.515 30.74 17.655 56.465 ;
        RECT 11.155 30.74 17.685 45.78 ;
        RECT 11.155 30.74 13.325 56.435 ;
        RECT 11.155 0 13.305 56.445 ;
        RECT 11.205 0 13.295 56.495 ;
        RECT 11.155 0 13.295 56.465 ;
        RECT 9.795 0 13.305 38.51 ;
        RECT 6.795 30.74 8.965 56.445 ;
        RECT 6.845 30.74 8.935 56.495 ;
        RECT 3.415 0 6.925 45.78 ;
        RECT 6.795 30.74 8.935 56.465 ;
        RECT 2.435 43.88 4.605 56.445 ;
        RECT 2.485 43.85 4.575 56.495 ;
        RECT 3.015 43.3 8.965 45.78 ;
        RECT 3.365 42.95 4.575 56.495 ;
        RECT 3.065 43.25 8.965 45.78 ;
        RECT 3.315 43 4.575 56.495 ;
        RECT 3.115 43.2 8.965 45.78 ;
        RECT 3.265 43.05 4.575 56.495 ;
        RECT 3.165 43.15 8.965 45.78 ;
        RECT 3.215 43.1 4.575 56.495 ;
        RECT 2.435 43.88 4.575 56.465 ;
      LAYER metal2 ;
        RECT 50.395 43.9 52.565 56.445 ;
        RECT 50.445 43.85 52.535 56.495 ;
        RECT 2.515 43.8 52.485 45.78 ;
        RECT 2.565 43.75 52.435 45.78 ;
        RECT 2.615 43.7 52.385 45.78 ;
        RECT 2.665 43.65 52.335 45.78 ;
        RECT 2.715 43.6 52.285 45.78 ;
        RECT 2.765 43.55 52.235 45.78 ;
        RECT 2.815 43.5 52.185 45.78 ;
        RECT 2.865 43.45 52.135 45.78 ;
        RECT 2.915 43.4 52.085 45.78 ;
        RECT 2.965 43.35 52.035 45.78 ;
        RECT 3.015 43.33 51.985 45.78 ;
        RECT 50.445 43.3 51.985 56.495 ;
        RECT 46.035 43.25 51.935 45.78 ;
        RECT 46.035 43.2 51.885 45.78 ;
        RECT 46.035 43.15 51.835 45.78 ;
        RECT 46.035 43.1 51.785 45.78 ;
        RECT 46.035 43.05 51.735 45.78 ;
        RECT 46.035 43 51.685 45.78 ;
        RECT 46.035 42.95 51.635 45.78 ;
        RECT 50.395 43.85 52.535 56.465 ;
        RECT 48.075 0 51.585 45.78 ;
        RECT 46.035 30.74 48.205 56.445 ;
        RECT 46.085 30.74 48.175 56.495 ;
        RECT 3.415 0 51.585 2 ;
        RECT 46.035 30.74 48.175 56.465 ;
        RECT 3.415 30.74 51.585 38.51 ;
        RECT 41.695 0 45.205 38.51 ;
        RECT 41.695 0 43.845 56.445 ;
        RECT 41.745 0 43.815 56.495 ;
        RECT 41.695 0 43.815 56.485 ;
        RECT 41.675 30.74 43.845 56.435 ;
        RECT 37.315 30.74 43.845 45.78 ;
        RECT 37.315 30.74 39.485 56.445 ;
        RECT 37.365 30.74 39.455 56.495 ;
        RECT 35.315 0 38.825 38.51 ;
        RECT 37.315 30.74 39.455 56.465 ;
        RECT 32.955 30.74 35.125 56.445 ;
        RECT 33.005 30.74 35.095 56.495 ;
        RECT 32.955 30.74 35.095 56.465 ;
        RECT 28.595 30.74 35.125 45.78 ;
        RECT 28.935 0 32.445 45.78 ;
        RECT 28.595 30.74 30.765 56.445 ;
        RECT 28.645 30.74 30.735 56.495 ;
        RECT 28.595 30.74 30.735 56.465 ;
        RECT 24.235 30.74 26.405 56.445 ;
        RECT 24.285 30.74 26.375 56.495 ;
        RECT 22.555 0 26.065 45.78 ;
        RECT 24.235 30.74 26.375 56.465 ;
        RECT 19.875 30.74 26.405 45.78 ;
        RECT 19.875 30.74 22.045 56.445 ;
        RECT 19.925 30.74 22.015 56.495 ;
        RECT 19.875 30.74 22.015 56.465 ;
        RECT 16.175 0 19.685 38.51 ;
        RECT 15.515 30.74 17.685 56.445 ;
        RECT 15.565 30.74 17.655 56.495 ;
        RECT 15.515 30.74 17.655 56.465 ;
        RECT 11.155 30.74 17.685 45.78 ;
        RECT 11.155 30.74 13.325 56.435 ;
        RECT 11.155 0 13.305 56.445 ;
        RECT 11.205 0 13.295 56.495 ;
        RECT 11.155 0 13.295 56.465 ;
        RECT 9.795 0 13.305 38.51 ;
        RECT 6.795 30.74 8.965 56.445 ;
        RECT 6.845 30.74 8.935 56.495 ;
        RECT 3.415 0 6.925 45.78 ;
        RECT 6.795 30.74 8.935 56.465 ;
        RECT 2.435 43.88 4.605 56.445 ;
        RECT 2.485 43.85 4.575 56.495 ;
        RECT 3.015 43.3 8.965 45.78 ;
        RECT 3.365 42.95 4.575 56.495 ;
        RECT 3.065 43.25 8.965 45.78 ;
        RECT 3.315 43 4.575 56.495 ;
        RECT 3.115 43.2 8.965 45.78 ;
        RECT 3.265 43.05 4.575 56.495 ;
        RECT 3.165 43.15 8.965 45.78 ;
        RECT 3.215 43.1 4.575 56.495 ;
        RECT 2.435 43.88 4.575 56.465 ;
    END
  END PAD
  OBS
    LAYER metal10 SPACING 0.4 ;
      RECT 0 0 55 80 ;
    LAYER via9 ;
      RECT 0 0 55 80 ;
    LAYER metal9 ;
      RECT 0 74.22 55 78.86 ;
      RECT 0 68.3 55 73.62 ;
      RECT 0 43.75 55 50.25 ;
      RECT 0 43.75 3 59.34 ;
      RECT 5.205 43.75 6.195 59.34 ;
      RECT 9.565 43.75 10.555 59.34 ;
      RECT 13.925 43.75 14.915 59.34 ;
      RECT 18.285 43.75 19.275 59.34 ;
      RECT 22.645 43.75 23.635 59.34 ;
      RECT 27.005 43.75 27.995 59.34 ;
      RECT 31.365 43.75 32.355 59.34 ;
      RECT 35.725 43.75 36.715 59.34 ;
      RECT 40.085 43.75 41.075 59.34 ;
      RECT 44.445 43.75 45.435 59.34 ;
      RECT 48.805 43.75 49.795 59.34 ;
      RECT 52 43.75 55 59.34 ;
      RECT 0 52.84 55 59.34 ;
      RECT 0 41.43 55 42.95 ;
      RECT 0 39.11 55 40.63 ;
      RECT 0 30.755 55 31.655 ;
      RECT 0 3.5 55 10.5 ;
      RECT 0 12.5 55 20.46 ;
      RECT 0 3.5 3 29.46 ;
      RECT 7.525 3.5 9.195 29.46 ;
      RECT 13.905 3.5 15.575 29.46 ;
      RECT 20.285 3.5 21.955 29.46 ;
      RECT 26.665 3.5 28.335 29.46 ;
      RECT 33.045 3.5 34.715 29.46 ;
      RECT 39.425 3.5 41.095 29.46 ;
      RECT 45.805 3.5 47.475 29.46 ;
      RECT 52 3.5 55 29.46 ;
      RECT 0 22.46 55 29.46 ;
    LAYER metal9 SPACING 0.4 ;
      RECT 0 0 2.785 80 ;
      RECT 0 2.63 55 78.86 ;
      RECT 0 2.63 8.475 80 ;
      RECT 15.085 2.63 20.27 80 ;
      RECT 23.49 2.63 28.3 80 ;
      RECT 52.215 0 55 80 ;
      RECT 31.52 2.63 55 80 ;
    LAYER via8 ;
      RECT 0 0 55 80 ;
    LAYER metal8 ;
      RECT 0 74.22 55 78.86 ;
      RECT 0 66.87 55 73.62 ;
      RECT 0 61.57 55 65.87 ;
      RECT 0 60.29 55 60.97 ;
      RECT 0 43.75 55 50.25 ;
      RECT 0 43.75 3 59.34 ;
      RECT 5.205 43.75 6.195 59.34 ;
      RECT 9.565 43.75 10.555 59.34 ;
      RECT 13.925 43.75 14.915 59.34 ;
      RECT 18.285 43.75 19.275 59.34 ;
      RECT 22.645 43.75 23.635 59.34 ;
      RECT 27.005 43.75 27.995 59.34 ;
      RECT 31.365 43.75 32.355 59.34 ;
      RECT 35.725 43.75 36.715 59.34 ;
      RECT 40.085 43.75 41.075 59.34 ;
      RECT 44.445 43.75 45.435 59.34 ;
      RECT 48.805 43.75 49.795 59.34 ;
      RECT 52 43.75 55 59.34 ;
      RECT 0 52.84 55 59.34 ;
      RECT 0 41.43 55 42.95 ;
      RECT 0 39.11 55 40.63 ;
      RECT 0 30.755 55 31.655 ;
      RECT 0 3.5 55 10.5 ;
      RECT 0 12.5 55 20.46 ;
      RECT 0 3.5 3 29.46 ;
      RECT 7.525 3.5 9.195 29.46 ;
      RECT 13.905 3.5 15.575 29.46 ;
      RECT 20.285 3.5 21.955 29.46 ;
      RECT 26.665 3.5 28.335 29.46 ;
      RECT 33.045 3.5 34.715 29.46 ;
      RECT 39.425 3.5 41.095 29.46 ;
      RECT 45.805 3.5 47.475 29.46 ;
      RECT 52 3.5 55 29.46 ;
      RECT 0 22.46 55 29.46 ;
    LAYER metal8 SPACING 0.1 ;
      RECT 0 0 3.085 80 ;
      RECT 0 2.33 55 79.13 ;
      RECT 0 2.33 8.775 80 ;
      RECT 11.395 2.33 12.165 80 ;
      RECT 14.785 2.33 20.57 80 ;
      RECT 23.19 2.33 28.6 80 ;
      RECT 51.915 0 55 80 ;
      RECT 31.22 2.33 55 80 ;
    LAYER via7 ;
      RECT 0 0 55 80 ;
    LAYER metal7 ;
      RECT 0 74.22 55 78.86 ;
      RECT 0 66.87 55 73.62 ;
      RECT 0 61.57 55 65.87 ;
      RECT 0 60.29 55 60.97 ;
      RECT 0 43.75 55 50.25 ;
      RECT 0 43.75 3 59.34 ;
      RECT 5.205 43.75 6.195 59.34 ;
      RECT 9.565 43.75 10.555 59.34 ;
      RECT 13.925 43.75 14.915 59.34 ;
      RECT 18.285 43.75 19.275 59.34 ;
      RECT 22.645 43.75 23.635 59.34 ;
      RECT 27.005 43.75 27.995 59.34 ;
      RECT 31.365 43.75 32.355 59.34 ;
      RECT 35.725 43.75 36.715 59.34 ;
      RECT 40.085 43.75 41.075 59.34 ;
      RECT 44.445 43.75 45.435 59.34 ;
      RECT 48.805 43.75 49.795 59.34 ;
      RECT 52 43.75 55 59.34 ;
      RECT 0 52.84 55 59.34 ;
      RECT 0 41.43 55 42.95 ;
      RECT 0 39.11 55 40.63 ;
      RECT 0 30.755 55 31.655 ;
      RECT 0 3.5 55 10.5 ;
      RECT 0 12.5 55 20.46 ;
      RECT 0 3.5 3 29.46 ;
      RECT 7.525 3.5 9.195 29.46 ;
      RECT 13.905 3.5 15.575 29.46 ;
      RECT 20.285 3.5 21.955 29.46 ;
      RECT 26.665 3.5 28.335 29.46 ;
      RECT 33.045 3.5 34.715 29.46 ;
      RECT 39.425 3.5 41.095 29.46 ;
      RECT 45.805 3.5 47.475 29.46 ;
      RECT 52 3.5 55 29.46 ;
      RECT 0 22.46 55 29.46 ;
    LAYER metal7 SPACING 0.1 ;
      RECT 0 0 3.24 80 ;
      RECT 0 2.175 55 79.285 ;
      RECT 0 2.175 8.93 80 ;
      RECT 11.24 2.175 12.32 80 ;
      RECT 14.63 2.175 20.725 80 ;
      RECT 23.035 2.175 28.755 80 ;
      RECT 51.76 0 55 80 ;
      RECT 31.065 2.175 55 80 ;
    LAYER via6 ;
      RECT 0 0 55 80 ;
    LAYER metal6 ;
      RECT 0 74.22 55 78.86 ;
      RECT 0 66.87 55 73.62 ;
      RECT 0 61.57 55 65.87 ;
      RECT 0 60.29 55 60.97 ;
      RECT 0 43.75 55 50.25 ;
      RECT 0 43.75 3 59.34 ;
      RECT 5.205 43.75 6.195 59.34 ;
      RECT 9.565 43.75 10.555 59.34 ;
      RECT 13.925 43.75 14.915 59.34 ;
      RECT 18.285 43.75 19.275 59.34 ;
      RECT 22.645 43.75 23.635 59.34 ;
      RECT 27.005 43.75 27.995 59.34 ;
      RECT 31.365 43.75 32.355 59.34 ;
      RECT 35.725 43.75 36.715 59.34 ;
      RECT 40.085 43.75 41.075 59.34 ;
      RECT 44.445 43.75 45.435 59.34 ;
      RECT 48.805 43.75 49.795 59.34 ;
      RECT 52 43.75 55 59.34 ;
      RECT 0 52.84 55 59.34 ;
      RECT 0 41.43 55 42.95 ;
      RECT 0 39.11 55 40.63 ;
      RECT 0 30.755 55 31.655 ;
      RECT 0 3.5 55 10.5 ;
      RECT 0 12.5 55 20.46 ;
      RECT 0 3.5 3 29.46 ;
      RECT 7.525 3.5 9.195 29.46 ;
      RECT 13.905 3.5 15.575 29.46 ;
      RECT 20.285 3.5 21.955 29.46 ;
      RECT 26.665 3.5 28.335 29.46 ;
      RECT 33.045 3.5 34.715 29.46 ;
      RECT 39.425 3.5 41.095 29.46 ;
      RECT 45.805 3.5 47.475 29.46 ;
      RECT 52 3.5 55 29.46 ;
      RECT 0 22.46 55 29.46 ;
    LAYER metal6 SPACING 0.1 ;
      RECT 0 0 3.24 80 ;
      RECT 0 2.175 55 79.285 ;
      RECT 0 2.175 8.93 80 ;
      RECT 11.24 2.175 12.32 80 ;
      RECT 14.63 2.175 20.725 80 ;
      RECT 23.035 2.175 28.755 80 ;
      RECT 51.76 0 55 80 ;
      RECT 31.065 2.175 55 80 ;
    LAYER via5 ;
      RECT 0 0 55 80 ;
    LAYER metal5 ;
      RECT 0 74.22 55 78.86 ;
      RECT 0 66.87 55 73.62 ;
      RECT 0 61.57 55 65.87 ;
      RECT 0 60.29 55 60.97 ;
      RECT 0 43.75 55 50.25 ;
      RECT 0 43.75 3 59.34 ;
      RECT 5.205 43.75 6.195 59.34 ;
      RECT 9.565 43.75 10.555 59.34 ;
      RECT 13.925 43.75 14.915 59.34 ;
      RECT 18.285 43.75 19.275 59.34 ;
      RECT 22.645 43.75 23.635 59.34 ;
      RECT 27.005 43.75 27.995 59.34 ;
      RECT 31.365 43.75 32.355 59.34 ;
      RECT 35.725 43.75 36.715 59.34 ;
      RECT 40.085 43.75 41.075 59.34 ;
      RECT 44.445 43.75 45.435 59.34 ;
      RECT 48.805 43.75 49.795 59.34 ;
      RECT 52 43.75 55 59.34 ;
      RECT 0 52.84 55 59.34 ;
      RECT 0 41.43 55 42.95 ;
      RECT 0 39.11 55 40.63 ;
      RECT 0 30.755 55 31.655 ;
      RECT 0 3.5 55 10.5 ;
      RECT 0 12.5 55 20.46 ;
      RECT 0 3.5 3 29.46 ;
      RECT 7.525 3.5 9.195 29.46 ;
      RECT 13.905 3.5 15.575 29.46 ;
      RECT 20.285 3.5 21.955 29.46 ;
      RECT 26.665 3.5 28.335 29.46 ;
      RECT 33.045 3.5 34.715 29.46 ;
      RECT 39.425 3.5 41.095 29.46 ;
      RECT 45.805 3.5 47.475 29.46 ;
      RECT 52 3.5 55 29.46 ;
      RECT 0 22.46 55 29.46 ;
    LAYER metal5 SPACING 0.1 ;
      RECT 0 0 3.24 80 ;
      RECT 0 2.175 55 79.285 ;
      RECT 0 2.175 8.93 80 ;
      RECT 11.24 2.175 12.32 80 ;
      RECT 14.63 2.175 20.725 80 ;
      RECT 23.035 2.175 28.755 80 ;
      RECT 51.76 0 55 80 ;
      RECT 31.065 2.175 55 80 ;
    LAYER via4 ;
      RECT 0 0 55 80 ;
    LAYER metal4 ;
      RECT 0 74.22 55 78.86 ;
      RECT 0 66.87 55 73.62 ;
      RECT 0 61.57 55 65.87 ;
      RECT 0 60.29 55 60.97 ;
      RECT 0 43.75 55 50.25 ;
      RECT 0 43.75 3 59.34 ;
      RECT 5.205 43.75 6.195 59.34 ;
      RECT 9.565 43.75 10.555 59.34 ;
      RECT 13.925 43.75 14.915 59.34 ;
      RECT 18.285 43.75 19.275 59.34 ;
      RECT 22.645 43.75 23.635 59.34 ;
      RECT 27.005 43.75 27.995 59.34 ;
      RECT 31.365 43.75 32.355 59.34 ;
      RECT 35.725 43.75 36.715 59.34 ;
      RECT 40.085 43.75 41.075 59.34 ;
      RECT 44.445 43.75 45.435 59.34 ;
      RECT 48.805 43.75 49.795 59.34 ;
      RECT 52 43.75 55 59.34 ;
      RECT 0 52.84 55 59.34 ;
      RECT 0 41.43 55 42.95 ;
      RECT 0 39.11 55 40.63 ;
      RECT 0 30.755 55 31.655 ;
      RECT 0 3.5 55 10.5 ;
      RECT 0 12.5 55 20.46 ;
      RECT 0 3.5 3 29.46 ;
      RECT 7.525 3.5 9.195 29.46 ;
      RECT 13.905 3.5 15.575 29.46 ;
      RECT 20.285 3.5 21.955 29.46 ;
      RECT 26.665 3.5 28.335 29.46 ;
      RECT 33.045 3.5 34.715 29.46 ;
      RECT 39.425 3.5 41.095 29.46 ;
      RECT 45.805 3.5 47.475 29.46 ;
      RECT 52 3.5 55 29.46 ;
      RECT 0 22.46 55 29.46 ;
    LAYER metal4 SPACING 0.1 ;
      RECT 0 0 3.24 80 ;
      RECT 0 2.175 55 79.285 ;
      RECT 0 2.175 8.93 80 ;
      RECT 11.24 2.175 12.32 80 ;
      RECT 14.63 2.175 20.725 80 ;
      RECT 23.035 2.175 28.755 80 ;
      RECT 51.76 0 55 80 ;
      RECT 31.065 2.175 55 80 ;
    LAYER via3 ;
      RECT 0 0 55 80 ;
    LAYER metal3 ;
      RECT 0 66.87 0.42 73.62 ;
      RECT 0 61.57 0.42 65.87 ;
      RECT 1.1 41.43 2.7 42.95 ;
      RECT 0 74.22 0.42 78.86 ;
      RECT 0 78.44 8.925 78.86 ;
      RECT 9.63 75.91 9.8 77.28 ;
      RECT 9.67 71.785 9.84 72.155 ;
      RECT 10.085 71.785 10.255 72.155 ;
      RECT 10.37 76.115 10.54 76.685 ;
      RECT 11.325 71.785 11.495 72.155 ;
      RECT 0.33 30.755 0.9 31.655 ;
      RECT 0.33 30.755 0.5 59.79 ;
      RECT 0.33 59.62 28.815 59.79 ;
      RECT 52.285 41.43 53.815 42.95 ;
      RECT 53.785 34.43 54.75 36.43 ;
      RECT 54.58 74.22 55 78.86 ;
      RECT 54.58 66.87 55 73.62 ;
      RECT 54.58 61.57 55 65.87 ;
    LAYER metal3 SPACING 0.1 ;
      RECT 7.1 2.175 9.62 30.565 ;
      RECT 9.14 38.685 10.98 43.155 ;
      RECT 13.48 2.175 16 30.565 ;
      RECT 17.86 38.685 19.7 43.155 ;
      RECT 19.86 2.175 22.38 30.565 ;
      RECT 26.58 38.685 28.42 43.155 ;
      RECT 26.24 2.175 28.76 30.565 ;
      RECT 32.62 2.175 35.14 30.565 ;
      RECT 35.3 38.685 37.14 43.155 ;
      RECT 39 2.175 41.52 30.565 ;
      RECT 44.02 38.685 45.86 43.155 ;
      RECT 45.38 2.175 47.9 30.565 ;
      RECT 0 0 3.24 42.775 ;
      RECT 51.76 0 55 42.775 ;
      RECT 0 0 3.19 42.825 ;
      RECT 51.81 0 55 42.825 ;
      RECT 0 0 3.14 42.875 ;
      RECT 51.86 0 55 42.875 ;
      RECT 0 0 3.09 42.925 ;
      RECT 51.91 0 55 42.925 ;
      RECT 0 0 3.04 42.975 ;
      RECT 51.96 0 55 42.975 ;
      RECT 0 0 2.99 43.025 ;
      RECT 52.01 0 55 43.025 ;
      RECT 0 0 2.94 43.075 ;
      RECT 52.06 0 55 43.075 ;
      RECT 0 0 2.89 43.125 ;
      RECT 52.11 0 55 43.125 ;
      RECT 0 0 2.84 43.175 ;
      RECT 52.16 0 55 43.175 ;
      RECT 0 0 2.79 43.225 ;
      RECT 52.21 0 55 43.225 ;
      RECT 0 0 2.74 43.275 ;
      RECT 52.26 0 55 43.275 ;
      RECT 0 0 2.69 43.325 ;
      RECT 52.31 0 55 43.325 ;
      RECT 0 0 2.64 43.375 ;
      RECT 52.36 0 55 43.375 ;
      RECT 0 0 2.59 43.425 ;
      RECT 52.41 0 55 43.425 ;
      RECT 0 0 2.54 43.475 ;
      RECT 52.46 0 55 43.475 ;
      RECT 0 0 2.49 43.525 ;
      RECT 52.51 0 55 43.525 ;
      RECT 0 0 2.44 43.575 ;
      RECT 52.56 0 55 43.575 ;
      RECT 0 0 2.39 43.625 ;
      RECT 52.61 0 55 43.625 ;
      RECT 0 0 2.34 43.675 ;
      RECT 52.66 0 55 43.675 ;
      RECT 0 0 2.31 43.705 ;
      RECT 52.71 0 55 43.725 ;
      RECT 39.66 45.955 41.5 80 ;
      RECT 13.48 56.61 15.34 74.925 ;
      RECT 22.22 45.955 24.06 79.285 ;
      RECT 0 0 2.26 80 ;
      RECT 4.78 45.955 6.62 80 ;
      RECT 4.75 56.62 6.62 80 ;
      RECT 9.14 45.955 10.98 72.545 ;
      RECT 9.11 56.62 10.98 72.545 ;
      RECT 13.5 45.955 15.34 74.925 ;
      RECT 13.47 56.62 15.34 74.925 ;
      RECT 17.86 45.955 19.7 80 ;
      RECT 17.83 56.62 19.7 80 ;
      RECT 22.19 56.62 24.06 79.285 ;
      RECT 26.58 45.955 28.42 80 ;
      RECT 26.55 56.62 28.42 80 ;
      RECT 35.3 45.955 37.14 80 ;
      RECT 35.27 56.62 37.14 80 ;
      RECT 44.02 45.955 45.86 80 ;
      RECT 43.99 56.62 45.86 80 ;
      RECT 48.38 45.955 50.22 80 ;
      RECT 48.35 56.62 50.22 80 ;
      RECT 39.66 56.61 41.52 80 ;
      RECT 39.63 56.62 41.52 80 ;
      RECT 0 56.64 2.31 80 ;
      RECT 4.75 56.64 6.67 80 ;
      RECT 9.11 56.64 11.03 72.545 ;
      RECT 13.47 56.64 15.39 74.925 ;
      RECT 17.83 56.64 19.75 80 ;
      RECT 22.19 56.64 24.11 79.285 ;
      RECT 26.55 56.64 28.47 80 ;
      RECT 30.91 56.64 32.83 79.285 ;
      RECT 35.27 56.64 37.19 80 ;
      RECT 39.63 56.66 41.57 80 ;
      RECT 43.99 56.64 45.91 80 ;
      RECT 48.35 56.64 50.27 80 ;
      RECT 52.71 56.62 55 80 ;
      RECT 0 56.67 55 72.545 ;
      RECT 11.705 56.67 55 74.925 ;
      RECT 10.345 73.065 55 74.925 ;
      RECT 30.91 56.62 32.78 79.285 ;
      RECT 15.62 56.67 55 79.285 ;
      RECT 0 56.67 9.825 79.285 ;
      RECT 30.94 45.955 32.78 79.285 ;
      RECT 10.345 75.445 55 79.285 ;
      RECT 0 56.67 8.93 80 ;
      RECT 11.24 75.445 12.32 80 ;
      RECT 14.63 75.445 20.725 80 ;
      RECT 23.035 56.67 28.755 80 ;
      RECT 52.74 0 55 80 ;
      RECT 31.065 56.67 55 80 ;
    LAYER via2 ;
      RECT 0 0 55 80 ;
    LAYER metal2 ;
      RECT 0 66.87 0.42 73.62 ;
      RECT 0 61.57 0.42 65.87 ;
      RECT 1.1 41.43 2.7 42.95 ;
      RECT 0.33 44.895 1.835 45.065 ;
      RECT 0.33 44.895 0.5 58.14 ;
      RECT 0.33 57.97 2.835 58.14 ;
      RECT 1.63 57.97 1.8 64.41 ;
      RECT 0.92 64.24 1.8 64.41 ;
      RECT 0.92 64.24 1.09 68.515 ;
      RECT 0.92 68.345 3.94 68.515 ;
      RECT 2.07 68.345 2.24 71.715 ;
      RECT 3.77 68.345 3.94 71.715 ;
      RECT 0 74.22 0.42 78.86 ;
      RECT 0 78.44 8.925 78.86 ;
      RECT 10.575 72.72 10.945 72.89 ;
      RECT 10.775 72.72 10.945 74.555 ;
      RECT 10.775 74.385 11.4 74.555 ;
      RECT 11.23 74.385 11.4 75.27 ;
      RECT 11.23 75.1 12.23 75.27 ;
      RECT 12.06 71.845 12.23 75.67 ;
      RECT 12.06 75.5 12.55 75.67 ;
      RECT 12.38 75.5 12.55 77.27 ;
      RECT 12.42 71.785 12.59 72.355 ;
      RECT 15.115 72.72 15.485 72.89 ;
      RECT 15.115 72.72 15.285 75.27 ;
      RECT 15.075 75.1 15.445 75.27 ;
      RECT 14.87 71.845 15.04 72.415 ;
      RECT 14.87 72.245 15.855 72.415 ;
      RECT 15.685 72.72 16.74 72.89 ;
      RECT 16.47 72.72 16.64 75.27 ;
      RECT 15.685 75.1 16.74 75.27 ;
      RECT 15.685 72.245 15.855 75.9 ;
      RECT 14.55 75.73 15.855 75.9 ;
      RECT 14.55 75.73 14.72 76.7 ;
      RECT 22.175 75.5 22.345 77.27 ;
      RECT 28.7 71.845 28.87 72.415 ;
      RECT 29.385 71.915 29.555 72.285 ;
      RECT 29.745 71.93 29.915 72.3 ;
      RECT 29.67 72.13 29.84 74.215 ;
      RECT 23.225 74.045 29.84 74.215 ;
      RECT 23.225 74.045 23.395 76.7 ;
      RECT 29.98 73.73 30.15 74.1 ;
      RECT 29.77 64.64 29.94 65.93 ;
      RECT 28.39 65.76 29.94 65.93 ;
      RECT 28.39 65.76 28.56 70.83 ;
      RECT 28.39 70.66 30.22 70.83 ;
      RECT 29.06 70.66 29.23 73.925 ;
      RECT 22.495 73.755 29.23 73.925 ;
      RECT 22.495 73.755 22.665 77.27 ;
      RECT 35.12 70.005 35.29 72.51 ;
      RECT 34.615 72.34 35.29 72.51 ;
      RECT 34.615 72.34 34.785 72.89 ;
      RECT 30.8 72.72 34.785 72.89 ;
      RECT 30.8 72.72 30.97 75.27 ;
      RECT 30.77 75.1 31.65 75.27 ;
      RECT 31.48 75.1 31.65 75.935 ;
      RECT 31.48 75.765 33.15 75.935 ;
      RECT 31.7 75.765 31.87 76.185 ;
      RECT 32.34 75.765 32.51 76.185 ;
      RECT 32.98 75.765 33.15 76.185 ;
      RECT 36.2 70.005 36.37 72.175 ;
      RECT 35.62 72.005 36.37 72.175 ;
      RECT 35.62 72.005 35.79 72.89 ;
      RECT 34.935 72.72 35.79 72.89 ;
      RECT 35.07 72.72 35.24 75.27 ;
      RECT 33.01 75.1 35.24 75.27 ;
      RECT 34.47 75.1 34.64 76.15 ;
      RECT 52.285 41.43 53.815 42.95 ;
      RECT 54.58 34.43 54.75 59.32 ;
      RECT 48.72 59.15 54.75 59.32 ;
      RECT 48.72 59.15 48.89 63.26 ;
      RECT 44.465 63.09 48.895 63.26 ;
      RECT 44.465 63.09 44.635 64.06 ;
      RECT 45.885 63.09 46.055 64.06 ;
      RECT 47.305 63.09 47.475 64.06 ;
      RECT 48.725 63.09 48.895 64.06 ;
      RECT 54.58 74.22 55 78.86 ;
      RECT 54.58 66.87 55 73.62 ;
      RECT 54.58 61.57 55 65.87 ;
    LAYER metal2 SPACING 0.1 ;
      RECT 7.1 2.175 9.62 30.565 ;
      RECT 9.14 38.685 10.98 43.155 ;
      RECT 13.48 2.175 16 30.565 ;
      RECT 17.86 38.685 19.7 43.155 ;
      RECT 19.86 2.175 22.38 30.565 ;
      RECT 26.58 38.685 28.42 43.155 ;
      RECT 26.24 2.175 28.76 30.565 ;
      RECT 32.62 2.175 35.14 30.565 ;
      RECT 35.3 38.685 37.14 43.155 ;
      RECT 39 2.175 41.52 30.565 ;
      RECT 44.02 38.685 45.86 43.155 ;
      RECT 45.38 2.175 47.9 30.565 ;
      RECT 0 0 3.24 42.775 ;
      RECT 51.76 0 55 42.775 ;
      RECT 0 0 3.19 42.825 ;
      RECT 51.81 0 55 42.825 ;
      RECT 0 0 3.14 42.875 ;
      RECT 51.86 0 55 42.875 ;
      RECT 0 0 3.09 42.925 ;
      RECT 51.91 0 55 42.925 ;
      RECT 0 0 3.04 42.975 ;
      RECT 51.96 0 55 42.975 ;
      RECT 0 0 2.99 43.025 ;
      RECT 52.01 0 55 43.025 ;
      RECT 0 0 2.94 43.075 ;
      RECT 52.06 0 55 43.075 ;
      RECT 0 0 2.89 43.125 ;
      RECT 52.11 0 55 43.125 ;
      RECT 0 0 2.84 43.175 ;
      RECT 52.16 0 55 43.175 ;
      RECT 0 0 2.79 43.225 ;
      RECT 52.21 0 55 43.225 ;
      RECT 0 0 2.74 43.275 ;
      RECT 52.26 0 55 43.275 ;
      RECT 0 0 2.69 43.325 ;
      RECT 52.31 0 55 43.325 ;
      RECT 0 0 2.64 43.375 ;
      RECT 52.36 0 55 43.375 ;
      RECT 0 0 2.59 43.425 ;
      RECT 52.41 0 55 43.425 ;
      RECT 0 0 2.54 43.475 ;
      RECT 52.46 0 55 43.475 ;
      RECT 0 0 2.49 43.525 ;
      RECT 52.51 0 55 43.525 ;
      RECT 0 0 2.44 43.575 ;
      RECT 52.56 0 55 43.575 ;
      RECT 0 0 2.39 43.625 ;
      RECT 52.61 0 55 43.625 ;
      RECT 0 0 2.34 43.675 ;
      RECT 52.66 0 55 43.675 ;
      RECT 0 0 2.31 43.705 ;
      RECT 52.71 0 55 43.725 ;
      RECT 13.5 45.955 15.34 72.545 ;
      RECT 39.66 45.955 41.5 80 ;
      RECT 13.48 56.61 15.34 72.545 ;
      RECT 0 0 2.26 80 ;
      RECT 4.78 45.955 6.62 80 ;
      RECT 4.75 56.62 6.62 80 ;
      RECT 9.14 45.955 10.98 79.285 ;
      RECT 9.11 56.62 10.98 79.285 ;
      RECT 13.47 56.62 15.34 72.545 ;
      RECT 17.86 45.955 19.7 80 ;
      RECT 17.83 56.62 19.7 80 ;
      RECT 22.22 45.955 24.06 72.545 ;
      RECT 22.19 56.62 24.06 72.545 ;
      RECT 26.58 45.955 28.42 72.545 ;
      RECT 26.55 56.62 28.42 72.545 ;
      RECT 30.94 45.955 32.78 71.83 ;
      RECT 30.91 56.62 32.78 71.83 ;
      RECT 35.3 45.955 37.14 80 ;
      RECT 35.27 56.62 37.14 80 ;
      RECT 44.02 45.955 45.86 80 ;
      RECT 43.99 56.62 45.86 80 ;
      RECT 48.38 45.955 50.22 80 ;
      RECT 48.35 56.62 50.22 80 ;
      RECT 39.66 56.61 41.52 80 ;
      RECT 39.63 56.62 41.52 80 ;
      RECT 0 56.64 2.31 80 ;
      RECT 4.75 56.64 6.67 80 ;
      RECT 9.11 56.64 11.03 79.285 ;
      RECT 13.47 56.64 15.39 72.545 ;
      RECT 17.83 56.64 19.75 80 ;
      RECT 22.19 56.64 24.11 72.545 ;
      RECT 26.55 56.64 28.47 72.545 ;
      RECT 30.91 56.64 32.83 71.83 ;
      RECT 35.27 56.64 37.19 80 ;
      RECT 39.63 56.66 41.57 80 ;
      RECT 43.99 56.64 45.91 80 ;
      RECT 48.35 56.64 50.27 80 ;
      RECT 0 56.67 55 69.83 ;
      RECT 0 56.67 33.515 71.83 ;
      RECT 34.035 56.67 34.235 71.83 ;
      RECT 34.755 56.67 55 80 ;
      RECT 34.615 72.34 55 80 ;
      RECT 0 56.67 30.2 72.545 ;
      RECT 12.975 56.67 14.25 74.925 ;
      RECT 12.775 73.065 14.45 74.925 ;
      RECT 14.97 56.67 21.97 74.925 ;
      RECT 0 56.67 12.255 79.285 ;
      RECT 22.49 73.065 30.2 75.59 ;
      RECT 29.035 56.67 30.2 75.59 ;
      RECT 30.72 72.35 55 75.59 ;
      RECT 22.14 75.445 28.965 79.285 ;
      RECT 29.485 76.11 29.605 79.285 ;
      RECT 30.765 76.11 30.885 79.285 ;
      RECT 52.71 56.62 55 80 ;
      RECT 31.405 72.35 55 80 ;
      RECT 0 75.445 13.215 79.285 ;
      RECT 15.01 56.67 21.62 79.285 ;
      RECT 13.735 75.445 21.62 79.285 ;
      RECT 22.14 76.36 29.65 79.285 ;
      RECT 30.17 76.36 55 79.285 ;
      RECT 0 56.67 8.93 80 ;
      RECT 11.24 75.445 12.32 80 ;
      RECT 14.63 75.445 20.725 80 ;
      RECT 23.035 73.065 28.755 80 ;
      RECT 52.74 0 55 80 ;
      RECT 31.065 76.36 55 80 ;
    LAYER via1 ;
      RECT 0 0 55 80 ;
    LAYER metal1 ;
      RECT 0 74.22 55 74.64 ;
      RECT 18.82 74.22 19.22 75.02 ;
      RECT 19.98 74.22 20.38 75.02 ;
      RECT 24.315 74.22 24.715 75.02 ;
      RECT 25.475 74.22 25.875 75.02 ;
      RECT 26.635 74.22 27.035 75.02 ;
      RECT 44.935 74.22 45.335 75.02 ;
      RECT 46.095 74.22 46.495 75.02 ;
      RECT 47.255 74.22 47.655 75.02 ;
      RECT 48.415 74.22 48.815 75.02 ;
      RECT 49.575 74.22 49.975 75.02 ;
      RECT 50.735 74.22 51.135 75.02 ;
      RECT 51.895 74.22 52.295 75.02 ;
      RECT 53.055 74.22 53.455 75.02 ;
      RECT 0.92 74.22 1.32 75.075 ;
      RECT 2.08 74.22 2.48 75.075 ;
      RECT 3.24 74.22 3.64 75.075 ;
      RECT 4.4 74.22 4.8 75.075 ;
      RECT 5.56 74.22 5.96 75.075 ;
      RECT 6.72 74.22 7.12 75.075 ;
      RECT 42.19 75.73 42.36 77.05 ;
      RECT 0 74.22 0.42 78.86 ;
      RECT 0.92 78.075 1.32 78.86 ;
      RECT 2.08 78.075 2.48 78.86 ;
      RECT 3.24 78.075 3.64 78.86 ;
      RECT 4.4 78.075 4.8 78.86 ;
      RECT 5.56 78.075 5.96 78.86 ;
      RECT 6.72 78.075 7.12 78.86 ;
      RECT 7.62 74.22 8.12 78.86 ;
      RECT 8.99 75.73 9.16 78.86 ;
      RECT 9.63 75.73 9.8 78.86 ;
      RECT 10.37 75.71 10.54 78.86 ;
      RECT 11.01 75.71 11.18 78.86 ;
      RECT 11.65 75.71 11.82 78.86 ;
      RECT 12.06 75.73 12.23 78.86 ;
      RECT 15.19 75.73 15.36 78.86 ;
      RECT 16.15 75.51 16.32 78.86 ;
      RECT 16.79 75.73 16.96 78.86 ;
      RECT 17.735 74.22 18.235 78.86 ;
      RECT 18.82 78.02 19.22 78.86 ;
      RECT 19.98 78.02 20.38 78.86 ;
      RECT 20.985 74.22 21.485 78.86 ;
      RECT 22.175 75.5 22.345 78.86 ;
      RECT 22.905 75.73 23.075 78.86 ;
      RECT 24.315 78.02 24.715 78.86 ;
      RECT 25.475 78.02 25.875 78.86 ;
      RECT 26.635 78.02 27.035 78.86 ;
      RECT 27.855 74.22 28.355 78.86 ;
      RECT 28.82 75.73 28.99 78.86 ;
      RECT 29.46 75.73 29.63 78.86 ;
      RECT 30.1 75.73 30.27 78.86 ;
      RECT 30.74 75.73 30.91 78.86 ;
      RECT 31.38 75.73 31.55 78.86 ;
      RECT 32.02 75.73 32.19 78.86 ;
      RECT 32.66 75.73 32.83 78.86 ;
      RECT 33.3 75.73 33.47 78.86 ;
      RECT 34.15 75.71 34.32 78.86 ;
      RECT 34.79 75.71 34.96 78.86 ;
      RECT 36.615 75.635 36.785 78.86 ;
      RECT 38.035 75.635 38.205 78.86 ;
      RECT 39.455 75.635 39.625 78.86 ;
      RECT 40.77 75.73 40.94 78.86 ;
      RECT 42.23 75.915 42.4 78.86 ;
      RECT 43.685 74.22 43.935 78.86 ;
      RECT 44.935 78.02 45.335 78.86 ;
      RECT 46.095 78.02 46.495 78.86 ;
      RECT 47.255 78.02 47.655 78.86 ;
      RECT 48.415 78.02 48.815 78.86 ;
      RECT 49.575 78.02 49.975 78.86 ;
      RECT 50.735 78.02 51.135 78.86 ;
      RECT 51.895 78.02 52.295 78.86 ;
      RECT 53.055 78.02 53.455 78.86 ;
      RECT 54.58 74.22 55 78.86 ;
      RECT 0 78.44 55 78.86 ;
      RECT 0 66.87 55 67.29 ;
      RECT 7.24 66.87 7.41 70.295 ;
      RECT 8.94 66.87 9.11 70.295 ;
      RECT 10.64 66.87 10.81 70.295 ;
      RECT 12.34 66.87 12.51 70.295 ;
      RECT 14.04 66.87 14.21 70.295 ;
      RECT 15.74 66.87 15.91 70.295 ;
      RECT 17.44 66.87 17.61 70.295 ;
      RECT 19.14 66.87 19.31 70.295 ;
      RECT 20.84 66.87 21.01 70.295 ;
      RECT 28.7 66.87 28.87 70.295 ;
      RECT 30.4 66.87 30.57 70.295 ;
      RECT 32.1 66.87 32.27 70.295 ;
      RECT 27.14 66.87 27.31 71.385 ;
      RECT 33.33 66.87 33.5 72.295 ;
      RECT 34.05 66.87 34.22 72.295 ;
      RECT 34.76 66.87 34.93 72.295 ;
      RECT 35.84 66.87 36.01 72.295 ;
      RECT 36.56 66.87 36.73 72.295 ;
      RECT 0 66.87 0.42 73.62 ;
      RECT 1.22 68.345 1.39 73.62 ;
      RECT 2.92 68.345 3.09 73.62 ;
      RECT 4.62 68.345 4.79 73.62 ;
      RECT 6.83 68.34 7 73.62 ;
      RECT 21.25 68.34 21.42 73.62 ;
      RECT 22.51 68.285 22.68 73.62 ;
      RECT 24.21 68.285 24.38 73.62 ;
      RECT 24.62 68.345 24.79 73.62 ;
      RECT 26.6 68.345 26.77 73.62 ;
      RECT 53.47 71.34 53.64 73.62 ;
      RECT 54.695 66.87 55 73.62 ;
      RECT 0 73.2 55 73.62 ;
      RECT 0 61.57 55 61.99 ;
      RECT 4.22 61.57 4.62 62.31 ;
      RECT 5.38 61.57 5.78 62.31 ;
      RECT 26.275 61.57 26.675 62.31 ;
      RECT 30.835 61.57 31.005 64.22 ;
      RECT 19.09 61.57 19.26 64.275 ;
      RECT 0.92 61.57 1.09 64.41 ;
      RECT 2.34 61.57 2.51 64.41 ;
      RECT 8.385 61.57 8.555 64.41 ;
      RECT 36.545 61.57 36.715 64.41 ;
      RECT 51.76 61.57 51.93 64.41 ;
      RECT 53.18 61.57 53.35 64.41 ;
      RECT 11.33 61.57 11.5 64.43 ;
      RECT 16.14 61.57 16.31 64.43 ;
      RECT 20.21 61.57 20.38 64.43 ;
      RECT 21.63 61.57 21.8 64.43 ;
      RECT 37.665 61.57 37.835 64.43 ;
      RECT 39.085 61.57 39.255 64.43 ;
      RECT 22.04 61.57 22.21 64.505 ;
      RECT 23.46 61.57 23.63 64.505 ;
      RECT 24.88 61.57 25.05 64.505 ;
      RECT 40.505 61.57 40.675 64.505 ;
      RECT 0 61.57 0.42 65.87 ;
      RECT 3.12 61.57 3.62 65.87 ;
      RECT 4.22 65.07 4.62 65.87 ;
      RECT 5.38 65.07 5.78 65.87 ;
      RECT 6.37 61.57 7.12 65.87 ;
      RECT 8.79 62.87 8.96 65.87 ;
      RECT 13.57 61.57 14.07 65.87 ;
      RECT 18.68 62.87 18.85 65.87 ;
      RECT 25.485 61.57 25.735 65.87 ;
      RECT 26.275 65.07 26.675 65.87 ;
      RECT 27.21 61.57 27.71 65.87 ;
      RECT 28.29 64.04 28.46 65.87 ;
      RECT 54.58 61.57 55 65.87 ;
      RECT 0 65.45 55 65.87 ;
      RECT 0 60.29 55 60.97 ;
      RECT 0 43.75 55 44.48 ;
      RECT 6.035 43.75 55 45.065 ;
      RECT 0 46.53 1.835 56.445 ;
      RECT 53.165 46.51 55 56.465 ;
      RECT 0 46.48 1.805 56.495 ;
      RECT 53.215 46.48 55 56.495 ;
      RECT 0 43.75 0.5 59.34 ;
      RECT 6.035 57.97 55 59.34 ;
      RECT 54.5 43.75 55 59.34 ;
      RECT 0 58.63 55 59.34 ;
      RECT 0 41.43 55 42.95 ;
      RECT 0 39.11 55 40.63 ;
      RECT 0 0 55 0.4 ;
      RECT 0 3.85 2.815 27.95 ;
      RECT 0 3.8 2.765 28 ;
      RECT 0 3.75 2.715 28.05 ;
      RECT 0 3.7 2.665 28.1 ;
      RECT 0 3.65 2.615 28.15 ;
      RECT 0 3.6 2.565 28.2 ;
      RECT 52.185 3.6 55 28.2 ;
      RECT 0 0 1.185 33.47 ;
      RECT 53.815 0 55 32.93 ;
      RECT 0 32.55 55 32.93 ;
      RECT 0 32.55 40.715 33.47 ;
      RECT 0 0 0.75 38.31 ;
      RECT 2.025 35.53 40.715 38.31 ;
      RECT 6.15 32.55 40.715 38.31 ;
      RECT 0 36.04 40.715 38.31 ;
      RECT 54.6 0 55 38.31 ;
      RECT 0 37.93 55 38.31 ;
    LAYER metal1 SPACING 0.09 ;
      RECT 0 0 55 79.295 ;
      RECT 0 0 8.94 80 ;
      RECT 11.23 0 12.33 80 ;
      RECT 14.62 0 20.735 80 ;
      RECT 23.025 0 28.765 80 ;
      RECT 31.055 0 55 80 ;
  END
END PAD2

MACRO PPAD
  CLASS PAD ;
  ORIGIN 0 0 ;
  FOREIGN PPAD 0 0 ;
  SIZE 55 BY 80 ;
  SYMMETRY X Y R90 ;
  SITE IOSite ;
  PIN VDD
    DIRECTION OUTPUT ;
    USE SIGNAL ;
    PORT
      LAYER metal1 ;
        RECT 0 74.22 0.42 78.86 ;
        RECT 0 75.98 2.855 78.86 ;
        RECT 3.755 75.635 4.445 80 ;
        RECT 6.355 75.635 7.045 80 ;
        RECT 8.955 75.635 9.645 80 ;
        RECT 11.555 75.635 12.245 80 ;
        RECT 14.155 75.635 14.845 80 ;
        RECT 16.755 75.635 17.445 80 ;
        RECT 19.355 75.635 20.045 80 ;
        RECT 21.955 75.635 22.645 80 ;
        RECT 24.555 75.635 25.245 80 ;
        RECT 27.155 75.635 27.845 80 ;
        RECT 29.755 75.635 30.445 80 ;
        RECT 32.355 75.635 33.045 80 ;
        RECT 34.955 75.635 35.645 80 ;
        RECT 37.555 75.635 38.245 80 ;
        RECT 40.155 75.635 40.845 80 ;
        RECT 42.755 75.635 43.445 80 ;
        RECT 45.355 75.635 46.045 80 ;
        RECT 47.955 75.635 48.645 80 ;
        RECT 3.28 77.9 50.735 80 ;
        RECT 50.555 75.635 51.245 78.86 ;
        RECT 52.145 75.98 55 78.86 ;
        RECT 54.58 74.22 55 78.86 ;
        RECT 0 77.9 55 78.86 ;
      LAYER metal2 ;
        RECT 0 74.22 55 78.86 ;
        RECT 51.535 0 52.485 29.15 ;
        RECT 51.585 0 52.435 29.2 ;
        RECT 2.515 0 52.485 2 ;
        RECT 3.28 74.22 50.735 80 ;
        RECT 5.105 73.37 49.905 80 ;
        RECT 48.955 0 49.905 80 ;
        RECT 5.105 61.075 49.905 65.475 ;
        RECT 5.105 47.625 49.905 54.97 ;
        RECT 46.375 0 47.325 54.97 ;
        RECT 43.59 47.625 46.86 80 ;
        RECT 43.795 0 44.745 80 ;
        RECT 41.215 0 42.165 54.97 ;
        RECT 38.87 47.625 42.14 80 ;
        RECT 38.635 0 39.585 54.97 ;
        RECT 34.15 47.625 37.42 80 ;
        RECT 36.055 0 37.005 80 ;
        RECT 33.475 0 34.425 54.97 ;
        RECT 29.43 47.625 32.7 80 ;
        RECT 30.895 0 31.845 80 ;
        RECT 28.315 0 29.265 54.97 ;
        RECT 24.71 47.625 27.98 80 ;
        RECT 25.735 0 26.685 80 ;
        RECT 23.155 0 24.105 54.97 ;
        RECT 19.99 47.625 23.26 80 ;
        RECT 20.575 0 21.525 80 ;
        RECT 17.995 0 18.945 54.97 ;
        RECT 15.27 47.625 18.54 80 ;
        RECT 15.415 0 16.365 80 ;
        RECT 10.55 47.625 13.82 80 ;
        RECT 12.835 0 13.785 80 ;
        RECT 10.255 0 11.205 54.97 ;
        RECT 7.675 0 8.625 54.97 ;
        RECT 5.105 47.625 8.455 80 ;
        RECT 5.105 0 6.045 80 ;
        RECT 5.095 0 6.045 29.11 ;
        RECT 2.515 0 3.465 29.15 ;
        RECT 2.565 0 3.415 29.2 ;
      LAYER metal3 ;
        RECT 0 74.22 55 78.86 ;
        RECT 51.535 0 52.485 29.15 ;
        RECT 51.585 0 52.435 29.2 ;
        RECT 2.515 0 52.485 2 ;
        RECT 3.28 74.22 50.735 80 ;
        RECT 5.105 73.37 49.905 80 ;
        RECT 48.955 0 49.905 80 ;
        RECT 5.105 61.075 49.905 65.475 ;
        RECT 5.105 47.625 49.905 54.97 ;
        RECT 46.375 0 47.325 54.97 ;
        RECT 43.59 47.625 46.86 80 ;
        RECT 43.795 0 44.745 80 ;
        RECT 41.215 0 42.165 54.97 ;
        RECT 38.87 47.625 42.14 80 ;
        RECT 38.635 0 39.585 54.97 ;
        RECT 34.15 47.625 37.42 80 ;
        RECT 36.055 0 37.005 80 ;
        RECT 33.475 0 34.425 54.97 ;
        RECT 29.43 47.625 32.7 80 ;
        RECT 30.895 0 31.845 80 ;
        RECT 28.315 0 29.265 54.97 ;
        RECT 24.71 47.625 27.98 80 ;
        RECT 25.735 0 26.685 80 ;
        RECT 23.155 0 24.105 54.97 ;
        RECT 19.99 47.625 23.26 80 ;
        RECT 20.575 0 21.525 80 ;
        RECT 17.995 0 18.945 54.97 ;
        RECT 15.27 47.625 18.54 80 ;
        RECT 15.415 0 16.365 80 ;
        RECT 10.55 47.625 13.82 80 ;
        RECT 12.835 0 13.785 80 ;
        RECT 10.255 0 11.205 54.97 ;
        RECT 7.675 0 8.625 54.97 ;
        RECT 5.105 47.625 8.455 80 ;
        RECT 5.105 0 6.045 80 ;
        RECT 5.095 0 6.045 29.11 ;
        RECT 2.515 0 3.465 29.15 ;
        RECT 2.565 0 3.415 29.2 ;
      LAYER metal4 ;
        RECT 0 74.22 55 78.86 ;
        RECT 3.28 74.22 50.735 80 ;
      LAYER metal5 ;
        RECT 0 74.22 55 78.86 ;
        RECT 3.28 74.22 50.735 80 ;
      LAYER metal6 ;
        RECT 0 74.22 55 78.86 ;
        RECT 3.28 74.22 50.735 80 ;
      LAYER metal7 ;
        RECT 0 74.22 55 78.86 ;
        RECT 3.28 74.22 50.735 80 ;
      LAYER metal8 ;
        RECT 0 74.22 55 78.86 ;
        RECT 3.28 74.22 50.735 80 ;
      LAYER metal9 ;
        RECT 0 74.22 55 78.86 ;
        RECT 3.28 74.22 50.735 80 ;
    END
  END VDD
  OBS
    LAYER metal10 SPACING 0.4 ;
      RECT 0 0 55 80 ;
    LAYER via9 ;
      RECT 0 0 55 80 ;
    LAYER metal9 ;
      RECT 3.415 0 51.585 2 ;
      RECT 0 68.3 55 73.62 ;
      RECT 0 43.75 55 50.05 ;
      RECT 0 43.75 3 59.34 ;
      RECT 9.26 43.75 10.86 59.34 ;
      RECT 17.98 43.75 19.58 59.34 ;
      RECT 26.7 43.75 28.3 59.34 ;
      RECT 35.42 43.75 37.02 59.34 ;
      RECT 44.14 43.75 45.74 59.34 ;
      RECT 52 43.75 55 59.34 ;
      RECT 0 53.145 55 59.34 ;
      RECT 0 41.43 55 42.95 ;
      RECT 0 39.11 55 40.63 ;
      RECT 0 30.755 55 31.655 ;
      RECT 0 3.5 55 10.315 ;
      RECT 0 13.09 55 19.74 ;
      RECT 0 3.5 2.515 29.46 ;
      RECT 3.965 3.5 4.595 29.46 ;
      RECT 6.545 3.5 7.175 29.46 ;
      RECT 9.125 3.5 9.755 29.46 ;
      RECT 11.705 3.5 12.335 29.46 ;
      RECT 14.285 3.5 14.915 29.46 ;
      RECT 16.865 3.5 17.495 29.46 ;
      RECT 19.445 3.5 20.075 29.46 ;
      RECT 22.025 3.5 22.655 29.46 ;
      RECT 24.605 3.5 25.235 29.46 ;
      RECT 27.185 3.5 27.815 29.46 ;
      RECT 29.765 3.5 30.395 29.46 ;
      RECT 32.345 3.5 32.975 29.46 ;
      RECT 34.925 3.5 35.555 29.46 ;
      RECT 37.505 3.5 38.135 29.46 ;
      RECT 40.085 3.5 40.715 29.46 ;
      RECT 42.665 3.5 43.295 29.46 ;
      RECT 45.245 3.5 45.875 29.46 ;
      RECT 47.825 3.5 48.455 29.46 ;
      RECT 50.405 3.5 51.035 29.46 ;
      RECT 52.485 3.5 55 29.46 ;
      RECT 0 22.46 55 29.46 ;
    LAYER metal9 SPACING 0.4 ;
      RECT 0 79.49 2.65 80 ;
      RECT 51.365 79.49 55 80 ;
      RECT 0 0 55 73.62 ;
    LAYER via8 ;
      RECT 0 0 55 80 ;
    LAYER metal8 ;
      RECT 3.415 0 51.585 2 ;
      RECT 0 66.87 55 73.62 ;
      RECT 0 61.57 55 65.87 ;
      RECT 0 60.29 55 60.97 ;
      RECT 0 43.75 55 50.05 ;
      RECT 0 43.75 3 59.34 ;
      RECT 9.26 43.75 10.86 59.34 ;
      RECT 17.98 43.75 19.58 59.34 ;
      RECT 26.7 43.75 28.3 59.34 ;
      RECT 35.42 43.75 37.02 59.34 ;
      RECT 44.14 43.75 45.74 59.34 ;
      RECT 52 43.75 55 59.34 ;
      RECT 0 53.145 55 59.34 ;
      RECT 0 41.43 55 42.95 ;
      RECT 0 39.11 55 40.63 ;
      RECT 0 30.755 55 31.655 ;
      RECT 0 3.5 55 10.315 ;
      RECT 0 13.09 55 19.74 ;
      RECT 0 3.5 2.515 29.46 ;
      RECT 3.965 3.5 4.595 29.46 ;
      RECT 6.545 3.5 7.175 29.46 ;
      RECT 9.125 3.5 9.755 29.46 ;
      RECT 11.705 3.5 12.335 29.46 ;
      RECT 14.285 3.5 14.915 29.46 ;
      RECT 16.865 3.5 17.495 29.46 ;
      RECT 19.445 3.5 20.075 29.46 ;
      RECT 22.025 3.5 22.655 29.46 ;
      RECT 24.605 3.5 25.235 29.46 ;
      RECT 27.185 3.5 27.815 29.46 ;
      RECT 29.765 3.5 30.395 29.46 ;
      RECT 32.345 3.5 32.975 29.46 ;
      RECT 34.925 3.5 35.555 29.46 ;
      RECT 37.505 3.5 38.135 29.46 ;
      RECT 40.085 3.5 40.715 29.46 ;
      RECT 42.665 3.5 43.295 29.46 ;
      RECT 45.245 3.5 45.875 29.46 ;
      RECT 47.825 3.5 48.455 29.46 ;
      RECT 50.405 3.5 51.035 29.46 ;
      RECT 52.485 3.5 55 29.46 ;
      RECT 0 22.46 55 29.46 ;
    LAYER metal8 SPACING 0.1 ;
      RECT 0 79.19 2.95 80 ;
      RECT 51.065 79.19 55 80 ;
      RECT 0 0 55 73.89 ;
    LAYER via7 ;
      RECT 0 0 55 80 ;
    LAYER metal7 ;
      RECT 3.415 0 51.585 2 ;
      RECT 0 66.87 55 73.62 ;
      RECT 0 61.57 55 65.87 ;
      RECT 0 60.29 55 60.97 ;
      RECT 0 43.75 55 50.05 ;
      RECT 0 43.75 3 59.34 ;
      RECT 9.26 43.75 10.86 59.34 ;
      RECT 17.98 43.75 19.58 59.34 ;
      RECT 26.7 43.75 28.3 59.34 ;
      RECT 35.42 43.75 37.02 59.34 ;
      RECT 44.14 43.75 45.74 59.34 ;
      RECT 52 43.75 55 59.34 ;
      RECT 0 53.145 55 59.34 ;
      RECT 0 41.43 55 42.95 ;
      RECT 0 39.11 55 40.63 ;
      RECT 0 30.755 55 31.655 ;
      RECT 0 3.5 55 10.315 ;
      RECT 0 13.09 55 19.74 ;
      RECT 0 3.5 2.515 29.46 ;
      RECT 3.965 3.5 4.595 29.46 ;
      RECT 6.545 3.5 7.175 29.46 ;
      RECT 9.125 3.5 9.755 29.46 ;
      RECT 11.705 3.5 12.335 29.46 ;
      RECT 14.285 3.5 14.915 29.46 ;
      RECT 16.865 3.5 17.495 29.46 ;
      RECT 19.445 3.5 20.075 29.46 ;
      RECT 22.025 3.5 22.655 29.46 ;
      RECT 24.605 3.5 25.235 29.46 ;
      RECT 27.185 3.5 27.815 29.46 ;
      RECT 29.765 3.5 30.395 29.46 ;
      RECT 32.345 3.5 32.975 29.46 ;
      RECT 34.925 3.5 35.555 29.46 ;
      RECT 37.505 3.5 38.135 29.46 ;
      RECT 40.085 3.5 40.715 29.46 ;
      RECT 42.665 3.5 43.295 29.46 ;
      RECT 45.245 3.5 45.875 29.46 ;
      RECT 47.825 3.5 48.455 29.46 ;
      RECT 50.405 3.5 51.035 29.46 ;
      RECT 52.485 3.5 55 29.46 ;
      RECT 0 22.46 55 29.46 ;
    LAYER metal7 SPACING 0.1 ;
      RECT 0 79.035 3.105 80 ;
      RECT 50.91 79.035 55 80 ;
      RECT 0 0 55 74.045 ;
    LAYER via6 ;
      RECT 0 0 55 80 ;
    LAYER metal6 ;
      RECT 3.415 0 51.585 2 ;
      RECT 0 66.87 55 73.62 ;
      RECT 0 61.57 55 65.87 ;
      RECT 0 60.29 55 60.97 ;
      RECT 0 43.75 55 50.05 ;
      RECT 0 43.75 3 59.34 ;
      RECT 9.26 43.75 10.86 59.34 ;
      RECT 17.98 43.75 19.58 59.34 ;
      RECT 26.7 43.75 28.3 59.34 ;
      RECT 35.42 43.75 37.02 59.34 ;
      RECT 44.14 43.75 45.74 59.34 ;
      RECT 52 43.75 55 59.34 ;
      RECT 0 53.145 55 59.34 ;
      RECT 0 41.43 55 42.95 ;
      RECT 0 39.11 55 40.63 ;
      RECT 0 30.755 55 31.655 ;
      RECT 0 3.5 55 10.315 ;
      RECT 0 13.09 55 19.74 ;
      RECT 0 3.5 2.515 29.46 ;
      RECT 3.965 3.5 4.595 29.46 ;
      RECT 6.545 3.5 7.175 29.46 ;
      RECT 9.125 3.5 9.755 29.46 ;
      RECT 11.705 3.5 12.335 29.46 ;
      RECT 14.285 3.5 14.915 29.46 ;
      RECT 16.865 3.5 17.495 29.46 ;
      RECT 19.445 3.5 20.075 29.46 ;
      RECT 22.025 3.5 22.655 29.46 ;
      RECT 24.605 3.5 25.235 29.46 ;
      RECT 27.185 3.5 27.815 29.46 ;
      RECT 29.765 3.5 30.395 29.46 ;
      RECT 32.345 3.5 32.975 29.46 ;
      RECT 34.925 3.5 35.555 29.46 ;
      RECT 37.505 3.5 38.135 29.46 ;
      RECT 40.085 3.5 40.715 29.46 ;
      RECT 42.665 3.5 43.295 29.46 ;
      RECT 45.245 3.5 45.875 29.46 ;
      RECT 47.825 3.5 48.455 29.46 ;
      RECT 50.405 3.5 51.035 29.46 ;
      RECT 52.485 3.5 55 29.46 ;
      RECT 0 22.46 55 29.46 ;
    LAYER metal6 SPACING 0.1 ;
      RECT 0 79.035 3.105 80 ;
      RECT 50.91 79.035 55 80 ;
      RECT 0 0 55 74.045 ;
    LAYER via5 ;
      RECT 0 0 55 80 ;
    LAYER metal5 ;
      RECT 3.415 0 51.585 2 ;
      RECT 0 66.87 55 73.62 ;
      RECT 0 61.57 55 65.87 ;
      RECT 0 60.29 55 60.97 ;
      RECT 0 43.75 55 50.05 ;
      RECT 0 43.75 3 59.34 ;
      RECT 9.26 43.75 10.86 59.34 ;
      RECT 17.98 43.75 19.58 59.34 ;
      RECT 26.7 43.75 28.3 59.34 ;
      RECT 35.42 43.75 37.02 59.34 ;
      RECT 44.14 43.75 45.74 59.34 ;
      RECT 52 43.75 55 59.34 ;
      RECT 0 53.145 55 59.34 ;
      RECT 0 41.43 55 42.95 ;
      RECT 0 39.11 55 40.63 ;
      RECT 0 30.755 55 31.655 ;
      RECT 0 3.5 55 10.315 ;
      RECT 0 13.09 55 19.74 ;
      RECT 0 3.5 2.515 29.46 ;
      RECT 3.965 3.5 4.595 29.46 ;
      RECT 6.545 3.5 7.175 29.46 ;
      RECT 9.125 3.5 9.755 29.46 ;
      RECT 11.705 3.5 12.335 29.46 ;
      RECT 14.285 3.5 14.915 29.46 ;
      RECT 16.865 3.5 17.495 29.46 ;
      RECT 19.445 3.5 20.075 29.46 ;
      RECT 22.025 3.5 22.655 29.46 ;
      RECT 24.605 3.5 25.235 29.46 ;
      RECT 27.185 3.5 27.815 29.46 ;
      RECT 29.765 3.5 30.395 29.46 ;
      RECT 32.345 3.5 32.975 29.46 ;
      RECT 34.925 3.5 35.555 29.46 ;
      RECT 37.505 3.5 38.135 29.46 ;
      RECT 40.085 3.5 40.715 29.46 ;
      RECT 42.665 3.5 43.295 29.46 ;
      RECT 45.245 3.5 45.875 29.46 ;
      RECT 47.825 3.5 48.455 29.46 ;
      RECT 50.405 3.5 51.035 29.46 ;
      RECT 52.485 3.5 55 29.46 ;
      RECT 0 22.46 55 29.46 ;
    LAYER metal5 SPACING 0.1 ;
      RECT 0 79.035 3.105 80 ;
      RECT 50.91 79.035 55 80 ;
      RECT 0 0 55 74.045 ;
    LAYER via4 ;
      RECT 0 0 55 80 ;
    LAYER metal4 ;
      RECT 3.415 0 51.585 2 ;
      RECT 0 66.87 55 73.62 ;
      RECT 0 61.57 55 65.87 ;
      RECT 0 60.29 55 60.97 ;
      RECT 0 43.75 55 50.05 ;
      RECT 0 43.75 3 59.34 ;
      RECT 9.26 43.75 10.86 59.34 ;
      RECT 17.98 43.75 19.58 59.34 ;
      RECT 26.7 43.75 28.3 59.34 ;
      RECT 35.42 43.75 37.02 59.34 ;
      RECT 44.14 43.75 45.74 59.34 ;
      RECT 52 43.75 55 59.34 ;
      RECT 0 53.145 55 59.34 ;
      RECT 0 41.43 55 42.95 ;
      RECT 0 39.11 55 40.63 ;
      RECT 0 30.755 55 31.655 ;
      RECT 0 3.5 55 10.315 ;
      RECT 0 13.09 55 19.74 ;
      RECT 0 3.5 2.515 29.46 ;
      RECT 3.965 3.5 4.595 29.46 ;
      RECT 6.545 3.5 7.175 29.46 ;
      RECT 9.125 3.5 9.755 29.46 ;
      RECT 11.705 3.5 12.335 29.46 ;
      RECT 14.285 3.5 14.915 29.46 ;
      RECT 16.865 3.5 17.495 29.46 ;
      RECT 19.445 3.5 20.075 29.46 ;
      RECT 22.025 3.5 22.655 29.46 ;
      RECT 24.605 3.5 25.235 29.46 ;
      RECT 27.185 3.5 27.815 29.46 ;
      RECT 29.765 3.5 30.395 29.46 ;
      RECT 32.345 3.5 32.975 29.46 ;
      RECT 34.925 3.5 35.555 29.46 ;
      RECT 37.505 3.5 38.135 29.46 ;
      RECT 40.085 3.5 40.715 29.46 ;
      RECT 42.665 3.5 43.295 29.46 ;
      RECT 45.245 3.5 45.875 29.46 ;
      RECT 47.825 3.5 48.455 29.46 ;
      RECT 50.405 3.5 51.035 29.46 ;
      RECT 52.485 3.5 55 29.46 ;
      RECT 0 22.46 55 29.46 ;
    LAYER metal4 SPACING 0.1 ;
      RECT 0 79.035 3.105 80 ;
      RECT 50.91 79.035 55 80 ;
      RECT 0 0 55 74.045 ;
    LAYER via3 ;
      RECT 0 0 55 80 ;
    LAYER metal3 ;
      RECT 0 66.87 0.42 73.62 ;
      RECT 0.33 30.755 0.9 31.655 ;
      RECT 1.385 2.65 2.015 29.15 ;
      RECT 1.435 2.6 1.965 29.2 ;
      RECT 0 61.57 3.425 65.87 ;
      RECT 3.965 2.65 4.595 29.15 ;
      RECT 4.015 2.6 4.545 29.2 ;
      RECT 6.595 2.6 7.125 47.025 ;
      RECT 6.545 2.65 7.175 47.025 ;
      RECT 9.175 2.6 9.705 47.025 ;
      RECT 9.125 2.65 9.755 47.025 ;
      RECT 11.755 2.6 12.285 47.025 ;
      RECT 11.705 2.65 12.335 47.025 ;
      RECT 14.335 2.6 14.865 47.025 ;
      RECT 14.285 2.65 14.915 47.025 ;
      RECT 16.915 2.6 17.445 47.025 ;
      RECT 16.865 2.65 17.495 47.025 ;
      RECT 19.495 2.6 20.025 47.025 ;
      RECT 19.445 2.65 20.075 47.025 ;
      RECT 22.075 2.6 22.605 47.025 ;
      RECT 22.025 2.65 22.655 47.025 ;
      RECT 24.655 2.6 25.185 47.025 ;
      RECT 24.605 2.65 25.235 47.025 ;
      RECT 27.235 2.6 27.765 47.025 ;
      RECT 27.185 2.65 27.815 47.025 ;
      RECT 29.815 2.6 30.345 47.025 ;
      RECT 29.765 2.65 30.395 47.025 ;
      RECT 32.395 2.6 32.925 47.025 ;
      RECT 32.345 2.65 32.975 47.025 ;
      RECT 34.975 2.6 35.505 47.025 ;
      RECT 34.925 2.65 35.555 47.025 ;
      RECT 37.555 2.6 38.085 47.025 ;
      RECT 37.505 2.65 38.135 47.025 ;
      RECT 40.135 2.6 40.665 47.025 ;
      RECT 40.085 2.65 40.715 47.025 ;
      RECT 42.715 2.6 43.245 47.025 ;
      RECT 42.665 2.65 43.295 47.025 ;
      RECT 45.295 2.6 45.825 47.025 ;
      RECT 45.245 2.65 45.875 47.025 ;
      RECT 47.875 2.6 48.405 47.025 ;
      RECT 47.825 2.65 48.455 47.025 ;
      RECT 50.455 2.6 50.985 47.025 ;
      RECT 50.405 2.65 51.035 47.025 ;
      RECT 52.985 2.65 53.615 29.15 ;
      RECT 53.035 2.6 53.565 29.2 ;
      RECT 54.58 66.87 55 73.62 ;
      RECT 51.575 61.57 55 65.87 ;
    LAYER metal3 SPACING 0.1 ;
      RECT 0 79.035 3.105 80 ;
      RECT 3.64 2.175 4.92 74.045 ;
      RECT 0 0 2.34 74.045 ;
      RECT 0 29.325 2.39 74.045 ;
      RECT 3.59 29.325 4.93 74.045 ;
      RECT 3.64 29.285 4.93 74.045 ;
      RECT 0 29.375 4.93 74.045 ;
      RECT 6.22 2.175 7.5 47.45 ;
      RECT 8.8 2.175 10.08 47.45 ;
      RECT 8.63 65.65 10.375 73.195 ;
      RECT 8.63 55.145 10.375 60.9 ;
      RECT 11.38 2.175 12.66 47.45 ;
      RECT 13.995 65.65 15.095 73.195 ;
      RECT 13.995 55.145 15.095 60.9 ;
      RECT 13.96 2.175 15.24 47.45 ;
      RECT 16.54 2.175 17.82 47.45 ;
      RECT 18.715 65.65 19.815 73.195 ;
      RECT 18.715 55.145 19.815 60.9 ;
      RECT 19.12 2.175 20.4 47.45 ;
      RECT 21.7 2.175 22.98 47.45 ;
      RECT 23.435 65.65 24.535 73.195 ;
      RECT 23.435 55.145 24.535 60.9 ;
      RECT 24.28 2.175 25.56 47.45 ;
      RECT 26.86 2.175 28.14 47.45 ;
      RECT 28.155 65.65 29.255 73.195 ;
      RECT 28.155 55.145 29.255 60.9 ;
      RECT 29.44 2.175 30.72 47.45 ;
      RECT 32.02 2.175 33.3 47.45 ;
      RECT 32.875 65.65 33.975 73.195 ;
      RECT 32.875 55.145 33.975 60.9 ;
      RECT 34.6 2.175 35.88 47.45 ;
      RECT 37.18 2.175 38.46 47.45 ;
      RECT 37.595 65.65 38.695 73.195 ;
      RECT 37.595 55.145 38.695 60.9 ;
      RECT 39.76 2.175 41.04 47.45 ;
      RECT 42.315 65.65 43.415 73.195 ;
      RECT 42.315 55.145 43.415 60.9 ;
      RECT 42.34 2.175 43.62 47.45 ;
      RECT 44.92 2.175 46.2 47.45 ;
      RECT 47.035 65.65 48.78 73.195 ;
      RECT 47.035 55.145 48.78 60.9 ;
      RECT 47.5 2.175 48.78 47.45 ;
      RECT 50.91 79.035 55 80 ;
      RECT 50.08 2.175 51.36 74.045 ;
      RECT 50.08 29.325 51.41 74.045 ;
      RECT 52.61 29.325 55 74.045 ;
      RECT 52.66 0 55 74.045 ;
      RECT 50.08 29.375 55 74.045 ;
    LAYER via2 ;
      RECT 0 0 55 80 ;
    LAYER metal2 ;
      RECT 0 66.87 0.42 73.62 ;
      RECT 0 61.57 0.5 65.87 ;
      RECT 1.385 2.65 2.015 29.15 ;
      RECT 1.435 2.6 1.965 29.2 ;
      RECT 3.605 30.595 4.105 74.12 ;
      RECT 3.965 2.65 4.595 29.15 ;
      RECT 4.015 2.6 4.545 29.2 ;
      RECT 6.595 2.6 7.125 47.025 ;
      RECT 6.545 2.65 7.175 47.025 ;
      RECT 9.175 2.6 9.705 47.025 ;
      RECT 9.125 2.65 9.755 47.025 ;
      RECT 11.755 2.6 12.285 47.025 ;
      RECT 11.705 2.65 12.335 47.025 ;
      RECT 14.335 2.6 14.865 47.025 ;
      RECT 14.285 2.65 14.915 47.025 ;
      RECT 16.915 2.6 17.445 47.025 ;
      RECT 16.865 2.65 17.495 47.025 ;
      RECT 19.495 2.6 20.025 47.025 ;
      RECT 19.445 2.65 20.075 47.025 ;
      RECT 22.075 2.6 22.605 47.025 ;
      RECT 22.025 2.65 22.655 47.025 ;
      RECT 24.655 2.6 25.185 47.025 ;
      RECT 24.605 2.65 25.235 47.025 ;
      RECT 27.235 2.6 27.765 47.025 ;
      RECT 27.185 2.65 27.815 47.025 ;
      RECT 29.815 2.6 30.345 47.025 ;
      RECT 29.765 2.65 30.395 47.025 ;
      RECT 32.395 2.6 32.925 47.025 ;
      RECT 32.345 2.65 32.975 47.025 ;
      RECT 34.975 2.6 35.505 47.025 ;
      RECT 34.925 2.65 35.555 47.025 ;
      RECT 37.555 2.6 38.085 47.025 ;
      RECT 37.505 2.65 38.135 47.025 ;
      RECT 40.135 2.6 40.665 47.025 ;
      RECT 40.085 2.65 40.715 47.025 ;
      RECT 42.715 2.6 43.245 47.025 ;
      RECT 42.665 2.65 43.295 47.025 ;
      RECT 45.295 2.6 45.825 47.025 ;
      RECT 45.245 2.65 45.875 47.025 ;
      RECT 47.875 2.6 48.405 47.025 ;
      RECT 47.825 2.65 48.455 47.025 ;
      RECT 50.455 2.6 50.985 47.025 ;
      RECT 50.405 2.65 51.035 47.025 ;
      RECT 52.86 30.595 53.36 74.12 ;
      RECT 52.985 2.65 53.615 29.15 ;
      RECT 53.035 2.6 53.565 29.2 ;
      RECT 54.58 66.87 55 73.62 ;
      RECT 54.5 61.57 55 65.87 ;
    LAYER metal2 SPACING 0.1 ;
      RECT 0 79.035 3.105 80 ;
      RECT 3.64 2.175 4.92 74.045 ;
      RECT 0 0 2.34 74.045 ;
      RECT 0 29.325 2.39 74.045 ;
      RECT 3.59 29.325 4.93 74.045 ;
      RECT 3.64 29.285 4.93 74.045 ;
      RECT 0 29.375 4.93 74.045 ;
      RECT 3.605 29.325 4.105 74.12 ;
      RECT 6.22 2.175 7.5 47.45 ;
      RECT 8.8 2.175 10.08 47.45 ;
      RECT 8.63 65.65 10.375 73.195 ;
      RECT 8.63 55.145 10.375 60.9 ;
      RECT 11.38 2.175 12.66 47.45 ;
      RECT 13.995 65.65 15.095 73.195 ;
      RECT 13.995 55.145 15.095 60.9 ;
      RECT 13.96 2.175 15.24 47.45 ;
      RECT 16.54 2.175 17.82 47.45 ;
      RECT 18.715 65.65 19.815 73.195 ;
      RECT 18.715 55.145 19.815 60.9 ;
      RECT 19.12 2.175 20.4 47.45 ;
      RECT 21.7 2.175 22.98 47.45 ;
      RECT 23.435 65.65 24.535 73.195 ;
      RECT 23.435 55.145 24.535 60.9 ;
      RECT 24.28 2.175 25.56 47.45 ;
      RECT 26.86 2.175 28.14 47.45 ;
      RECT 28.155 65.65 29.255 73.195 ;
      RECT 28.155 55.145 29.255 60.9 ;
      RECT 29.44 2.175 30.72 47.45 ;
      RECT 32.02 2.175 33.3 47.45 ;
      RECT 32.875 65.65 33.975 73.195 ;
      RECT 32.875 55.145 33.975 60.9 ;
      RECT 34.6 2.175 35.88 47.45 ;
      RECT 37.18 2.175 38.46 47.45 ;
      RECT 37.595 65.65 38.695 73.195 ;
      RECT 37.595 55.145 38.695 60.9 ;
      RECT 39.76 2.175 41.04 47.45 ;
      RECT 42.315 65.65 43.415 73.195 ;
      RECT 42.315 55.145 43.415 60.9 ;
      RECT 42.34 2.175 43.62 47.45 ;
      RECT 44.92 2.175 46.2 47.45 ;
      RECT 47.035 65.65 48.78 73.195 ;
      RECT 47.035 55.145 48.78 60.9 ;
      RECT 47.5 2.175 48.78 47.45 ;
      RECT 50.91 79.035 55 80 ;
      RECT 50.08 2.175 51.36 74.045 ;
      RECT 50.08 29.325 51.41 74.045 ;
      RECT 52.61 29.325 55 74.045 ;
      RECT 52.66 0 55 74.045 ;
      RECT 50.08 29.375 55 74.045 ;
      RECT 52.86 0 53.36 74.12 ;
    LAYER via1 ;
      RECT 0 0 55 80 ;
    LAYER metal1 ;
      RECT 0 41.43 3.3 42.95 ;
      RECT 1.3 41.43 3.3 43.885 ;
      RECT 0 61.57 3.425 61.97 ;
      RECT 0 61.57 0.5 65.87 ;
      RECT 1.275 61.57 1.525 65.87 ;
      RECT 2.225 61.57 2.475 65.87 ;
      RECT 3.175 61.57 3.425 65.87 ;
      RECT 0 65.47 3.425 65.87 ;
      RECT 0 39.11 5.54 40.63 ;
      RECT 4.1 39.11 5.54 43.885 ;
      RECT 0 0 2.015 29.15 ;
      RECT 0 0 1.965 29.2 ;
      RECT 0 0 0.59 38.31 ;
      RECT 0 32.49 9.755 38.31 ;
      RECT 6.33 32.49 9.755 43.09 ;
      RECT 6.33 32.49 8.33 43.885 ;
      RECT 0 60.29 45.92 60.97 ;
      RECT 3.465 0 5.095 2 ;
      RECT 6.045 0 7.675 2 ;
      RECT 8.625 0 10.255 2 ;
      RECT 11.205 0 12.835 2 ;
      RECT 13.785 0 15.415 2 ;
      RECT 16.365 0 17.995 2 ;
      RECT 18.945 0 20.575 2 ;
      RECT 21.525 0 23.155 2 ;
      RECT 24.105 0 25.735 2 ;
      RECT 26.685 0 28.315 2 ;
      RECT 29.265 0 30.895 2 ;
      RECT 31.845 0 33.475 2 ;
      RECT 34.425 0 36.055 2 ;
      RECT 37.005 0 38.635 2 ;
      RECT 39.585 0 41.215 2 ;
      RECT 42.165 0 43.795 2 ;
      RECT 44.745 0 46.375 2 ;
      RECT 47.325 0 48.955 2 ;
      RECT 49.905 0 51.535 2 ;
      RECT 2.615 0 3.365 29.2 ;
      RECT 5.195 0 5.945 29.2 ;
      RECT 7.775 0 8.525 29.2 ;
      RECT 10.355 0 11.105 29.2 ;
      RECT 12.935 0 13.685 29.2 ;
      RECT 15.515 0 16.265 29.2 ;
      RECT 18.095 0 18.845 29.2 ;
      RECT 20.675 0 21.425 29.2 ;
      RECT 23.255 0 24.005 29.2 ;
      RECT 25.835 0 26.585 29.2 ;
      RECT 28.415 0 29.165 29.2 ;
      RECT 30.995 0 31.745 29.2 ;
      RECT 33.575 0 34.325 29.2 ;
      RECT 36.155 0 36.905 29.2 ;
      RECT 38.735 0 39.485 29.2 ;
      RECT 41.315 0 42.065 29.2 ;
      RECT 43.895 0 44.645 29.2 ;
      RECT 46.475 0 47.225 29.2 ;
      RECT 49.055 0 49.805 29.2 ;
      RECT 51.635 0 52.385 29.2 ;
      RECT 52.385 0 52.435 29.2 ;
      RECT 52.435 0 52.485 29.15 ;
      RECT 51.535 0 51.585 29.15 ;
      RECT 51.585 0 51.635 29.2 ;
      RECT 49.805 0 49.855 29.2 ;
      RECT 49.855 0 49.905 29.15 ;
      RECT 48.955 0 49.005 29.15 ;
      RECT 49.005 0 49.055 29.2 ;
      RECT 47.225 0 47.275 29.2 ;
      RECT 47.275 0 47.325 29.15 ;
      RECT 46.375 0 46.425 29.15 ;
      RECT 46.425 0 46.475 29.2 ;
      RECT 44.645 0 44.695 29.2 ;
      RECT 44.695 0 44.745 29.15 ;
      RECT 43.795 0 43.845 29.15 ;
      RECT 43.845 0 43.895 29.2 ;
      RECT 42.065 0 42.115 29.2 ;
      RECT 42.115 0 42.165 29.15 ;
      RECT 41.215 0 41.265 29.15 ;
      RECT 41.265 0 41.315 29.2 ;
      RECT 39.485 0 39.535 29.2 ;
      RECT 39.535 0 39.585 29.15 ;
      RECT 38.635 0 38.685 29.15 ;
      RECT 38.685 0 38.735 29.2 ;
      RECT 36.905 0 36.955 29.2 ;
      RECT 36.955 0 37.005 29.15 ;
      RECT 36.055 0 36.105 29.15 ;
      RECT 36.105 0 36.155 29.2 ;
      RECT 34.325 0 34.375 29.2 ;
      RECT 34.375 0 34.425 29.15 ;
      RECT 33.475 0 33.525 29.15 ;
      RECT 33.525 0 33.575 29.2 ;
      RECT 31.745 0 31.795 29.2 ;
      RECT 31.795 0 31.845 29.15 ;
      RECT 30.895 0 30.945 29.15 ;
      RECT 30.945 0 30.995 29.2 ;
      RECT 29.165 0 29.215 29.2 ;
      RECT 29.215 0 29.265 29.15 ;
      RECT 28.315 0 28.365 29.15 ;
      RECT 28.365 0 28.415 29.2 ;
      RECT 26.585 0 26.635 29.2 ;
      RECT 26.635 0 26.685 29.15 ;
      RECT 25.735 0 25.785 29.15 ;
      RECT 25.785 0 25.835 29.2 ;
      RECT 24.005 0 24.055 29.2 ;
      RECT 24.055 0 24.105 29.15 ;
      RECT 23.155 0 23.205 29.15 ;
      RECT 23.205 0 23.255 29.2 ;
      RECT 21.425 0 21.475 29.2 ;
      RECT 21.475 0 21.525 29.15 ;
      RECT 20.575 0 20.625 29.15 ;
      RECT 20.625 0 20.675 29.2 ;
      RECT 18.845 0 18.895 29.2 ;
      RECT 18.895 0 18.945 29.15 ;
      RECT 17.995 0 18.045 29.15 ;
      RECT 18.045 0 18.095 29.2 ;
      RECT 16.265 0 16.315 29.2 ;
      RECT 16.315 0 16.365 29.15 ;
      RECT 15.415 0 15.465 29.15 ;
      RECT 15.465 0 15.515 29.2 ;
      RECT 13.685 0 13.735 29.2 ;
      RECT 13.735 0 13.785 29.15 ;
      RECT 12.835 0 12.885 29.15 ;
      RECT 12.885 0 12.935 29.2 ;
      RECT 11.105 0 11.155 29.2 ;
      RECT 11.155 0 11.205 29.15 ;
      RECT 10.255 0 10.305 29.15 ;
      RECT 10.305 0 10.355 29.2 ;
      RECT 8.525 0 8.575 29.2 ;
      RECT 8.575 0 8.625 29.15 ;
      RECT 7.675 0 7.725 29.15 ;
      RECT 7.725 0 7.775 29.2 ;
      RECT 5.945 0 5.995 29.2 ;
      RECT 5.995 0 6.045 29.15 ;
      RECT 5.095 0 5.145 29.15 ;
      RECT 5.145 0 5.195 29.2 ;
      RECT 3.365 0 3.415 29.2 ;
      RECT 3.415 0 3.465 29.15 ;
      RECT 2.515 0 2.565 29.15 ;
      RECT 2.565 0 2.615 29.2 ;
      RECT 1.01 73.82 4.105 74.12 ;
      RECT 52.85 73.82 53.99 74.12 ;
      RECT 1.01 73.82 1.31 75.48 ;
      RECT 53.69 73.82 53.99 75.48 ;
      RECT 1.01 75.18 53.99 75.48 ;
      RECT 5.055 75.18 5.745 77.3 ;
      RECT 7.655 75.18 8.345 77.3 ;
      RECT 10.255 75.18 10.945 77.3 ;
      RECT 12.855 75.18 13.545 77.3 ;
      RECT 15.455 75.18 16.145 77.3 ;
      RECT 18.055 75.18 18.745 77.3 ;
      RECT 20.655 75.18 21.345 77.3 ;
      RECT 23.255 75.18 23.945 77.3 ;
      RECT 25.855 75.18 26.545 77.3 ;
      RECT 28.455 75.18 29.145 77.3 ;
      RECT 31.055 75.18 31.745 77.3 ;
      RECT 33.655 75.18 34.345 77.3 ;
      RECT 36.255 75.18 36.945 77.3 ;
      RECT 38.855 75.18 39.545 77.3 ;
      RECT 41.455 75.18 42.145 77.3 ;
      RECT 44.055 75.18 44.745 77.3 ;
      RECT 46.655 75.18 47.345 77.3 ;
      RECT 49.255 75.18 49.945 77.3 ;
      RECT 46.46 57.27 46.86 61.99 ;
      RECT 6.965 61.57 48.025 61.99 ;
      RECT 6.965 63.87 48.025 66.87 ;
      RECT 0 66.87 7.965 67.37 ;
      RECT 47.025 66.87 55 67.37 ;
      RECT 0.945 66.87 1.345 67.775 ;
      RECT 2.145 66.87 2.545 67.775 ;
      RECT 3.345 66.87 3.745 67.775 ;
      RECT 4.545 66.87 4.945 67.775 ;
      RECT 5.745 66.87 6.145 67.775 ;
      RECT 48.825 66.87 49.225 67.775 ;
      RECT 50.025 66.87 50.425 67.775 ;
      RECT 51.225 66.87 51.625 67.775 ;
      RECT 6.965 68.285 48.025 71.285 ;
      RECT 47.025 61.57 48.025 72.025 ;
      RECT 8.985 62.74 9.155 72.11 ;
      RECT 12.335 62.74 12.505 72.11 ;
      RECT 15.685 62.74 15.855 72.11 ;
      RECT 19.035 62.74 19.205 72.11 ;
      RECT 22.385 62.74 22.555 72.11 ;
      RECT 25.735 62.74 25.905 72.11 ;
      RECT 29.085 62.74 29.255 72.11 ;
      RECT 32.435 62.74 32.605 72.11 ;
      RECT 35.785 62.74 35.955 72.11 ;
      RECT 39.135 62.74 39.305 72.11 ;
      RECT 42.485 62.74 42.655 72.11 ;
      RECT 45.835 62.74 46.005 72.11 ;
      RECT 52.435 66.87 52.605 72.14 ;
      RECT 53.695 66.87 53.865 72.14 ;
      RECT 6.965 61.57 7.965 72.15 ;
      RECT 0 66.87 0.42 73.62 ;
      RECT 0.945 72.85 1.345 73.62 ;
      RECT 2.145 72.85 2.545 73.62 ;
      RECT 3.345 72.85 3.745 73.62 ;
      RECT 4.545 72.85 4.945 73.62 ;
      RECT 5.745 72.85 6.145 73.62 ;
      RECT 48.825 72.85 49.225 73.62 ;
      RECT 50.025 72.85 50.425 73.62 ;
      RECT 51.225 72.85 51.625 73.62 ;
      RECT 0 73.2 7.965 73.62 ;
      RECT 54.58 66.87 55 73.62 ;
      RECT 47.035 73.2 55 73.62 ;
      RECT 51.575 61.57 55 61.97 ;
      RECT 51.575 61.57 51.825 65.87 ;
      RECT 52.525 61.57 52.775 65.87 ;
      RECT 53.475 61.57 53.725 65.87 ;
      RECT 54.5 61.57 55 65.87 ;
      RECT 51.575 65.47 55 65.87 ;
      RECT 47.365 60.29 55 60.97 ;
      RECT 0 49.225 55 50.025 ;
      RECT 53.28 49.075 53.68 50.275 ;
      RECT 0 43.75 0.8 59.34 ;
      RECT 0 59.09 45.92 59.34 ;
      RECT 54.2 43.75 55 59.34 ;
      RECT 47.385 59.09 55 59.34 ;
      RECT 51.7 41.43 55 42.95 ;
      RECT 51.7 41.43 53.7 43.885 ;
      RECT 49.46 39.11 55 40.63 ;
      RECT 49.46 39.11 50.9 43.885 ;
      RECT 52.985 0 55 29.15 ;
      RECT 53.035 0 55 29.2 ;
      RECT 54.41 0 55 38.31 ;
      RECT 45.245 32.49 55 38.31 ;
      RECT 45.245 32.49 48.67 43.09 ;
      RECT 46.67 32.49 48.67 43.885 ;
    LAYER metal1 SPACING 0.09 ;
      RECT 0 79.025 3.115 80 ;
      RECT 50.9 79.025 55 80 ;
      RECT 0 0 55 74.055 ;
      RECT 0.585 0 54.415 75.48 ;
      RECT 0.585 0 3.59 75.815 ;
      RECT 51.41 0 54.415 75.815 ;
      RECT 3.02 0 3.59 77.735 ;
      RECT 4.61 0 6.19 77.735 ;
      RECT 7.21 0 8.79 77.735 ;
      RECT 9.81 0 11.39 77.735 ;
      RECT 12.41 0 13.99 77.735 ;
      RECT 15.01 0 16.59 77.735 ;
      RECT 17.61 0 19.19 77.735 ;
      RECT 20.21 0 21.79 77.735 ;
      RECT 22.81 0 24.39 77.735 ;
      RECT 25.41 0 26.99 77.735 ;
      RECT 28.01 0 29.59 77.735 ;
      RECT 30.61 0 32.19 77.735 ;
      RECT 33.21 0 34.79 77.735 ;
      RECT 35.81 0 37.39 77.735 ;
      RECT 38.41 0 39.99 77.735 ;
      RECT 41.01 0 42.59 77.735 ;
      RECT 43.61 0 45.19 77.735 ;
      RECT 46.21 0 47.79 77.735 ;
      RECT 48.81 0 50.39 77.735 ;
      RECT 51.41 0 51.98 77.735 ;
  END
END PPAD
MACRO GPAD
  CLASS PAD ;
  ORIGIN 0 0 ;
  FOREIGN GPAD 0 0 ;
  SIZE 55 BY 80 ;
  SYMMETRY X Y R90 ;
  SITE IOSite ;
  PIN VSS
    DIRECTION OUTPUT ;
    USE SIGNAL ;
    PORT
      LAYER metal1 ;
        RECT 5.9 1.23 7.4 80 ;
        RECT 8.68 1.23 10.18 80 ;
        RECT 5.9 32.55 11.125 44.29 ;
        RECT 11.46 1.23 12.96 38.51 ;
        RECT 11.46 43.5 12.96 80 ;
        RECT 14.24 1.23 15.74 80 ;
        RECT 17.02 1.23 18.52 80 ;
        RECT 19.8 1.23 21.3 80 ;
        RECT 12.565 32.55 21.56 44.29 ;
        RECT 22.58 1.23 24.08 38.51 ;
        RECT 22.58 43.5 24.08 80 ;
        RECT 25.36 1.23 26.86 80 ;
        RECT 28.14 1.23 29.64 80 ;
        RECT 23 32.55 31.995 44.29 ;
        RECT 30.92 1.23 32.42 38.51 ;
        RECT 30.92 43.5 32.42 80 ;
        RECT 5.9 32.55 42.43 38.51 ;
        RECT 33.7 1.23 35.2 80 ;
        RECT 36.48 1.23 37.98 80 ;
        RECT 39.26 1.23 40.76 80 ;
        RECT 33.435 32.55 42.43 44.29 ;
        RECT 42.04 1.23 43.54 38.495 ;
        RECT 42.04 43.5 43.54 80 ;
        RECT 5.9 32.55 49.1 38.495 ;
        RECT 44.82 1.23 46.32 80 ;
        RECT 43.87 32.55 49.1 44.29 ;
        RECT 5.9 43.5 49.1 44.29 ;
        RECT 47.6 1.23 49.1 80 ;
        RECT 5.9 79.2 49.1 80 ;
      LAYER metal2 ;
        RECT 2.67 0 52.33 2 ;
        RECT 5.9 79.2 49.1 80 ;
        RECT 47.6 0 49.1 80 ;
        RECT 5.9 43.5 49.1 44.29 ;
        RECT 43.87 32.55 49.1 44.29 ;
        RECT 44.82 0 46.32 80 ;
        RECT 5.9 32.55 49.1 38.495 ;
        RECT 42.04 43.5 43.54 80 ;
        RECT 42.04 0 43.54 38.495 ;
        RECT 33.435 32.55 42.43 44.29 ;
        RECT 39.26 0 40.76 80 ;
        RECT 36.48 0 37.98 80 ;
        RECT 33.7 0 35.2 80 ;
        RECT 5.9 32.55 42.43 38.51 ;
        RECT 30.92 43.5 32.42 80 ;
        RECT 30.92 0 32.42 38.51 ;
        RECT 23 32.55 31.995 44.29 ;
        RECT 28.14 0 29.64 80 ;
        RECT 25.36 0 26.86 80 ;
        RECT 22.58 43.5 24.08 80 ;
        RECT 22.58 0 24.08 38.51 ;
        RECT 12.565 32.55 21.56 44.29 ;
        RECT 19.8 0 21.3 80 ;
        RECT 17.02 0 18.52 80 ;
        RECT 14.24 0 15.74 80 ;
        RECT 11.46 43.5 12.96 80 ;
        RECT 11.46 0 12.96 38.51 ;
        RECT 5.9 32.55 11.125 44.29 ;
        RECT 8.68 0 10.18 80 ;
        RECT 5.9 0 7.4 80 ;
      LAYER metal3 ;
        RECT 2.67 0 52.33 2 ;
        RECT 5.9 79.2 49.1 80 ;
        RECT 47.6 0 49.1 80 ;
        RECT 5.9 43.5 49.1 44.29 ;
        RECT 43.87 32.55 49.1 44.29 ;
        RECT 44.82 0 46.32 80 ;
        RECT 5.9 32.55 49.1 38.495 ;
        RECT 42.04 43.5 43.54 80 ;
        RECT 42.04 0 43.54 38.495 ;
        RECT 33.435 32.55 42.43 44.29 ;
        RECT 39.26 0 40.76 80 ;
        RECT 36.48 0 37.98 80 ;
        RECT 33.7 0 35.2 80 ;
        RECT 5.9 32.55 42.43 38.51 ;
        RECT 30.92 43.5 32.42 80 ;
        RECT 30.92 0 32.42 38.51 ;
        RECT 23 32.55 31.995 44.29 ;
        RECT 28.14 0 29.64 80 ;
        RECT 25.36 0 26.86 80 ;
        RECT 22.58 43.5 24.08 80 ;
        RECT 22.58 0 24.08 38.51 ;
        RECT 12.565 32.55 21.56 44.29 ;
        RECT 19.8 0 21.3 80 ;
        RECT 17.02 0 18.52 80 ;
        RECT 14.24 0 15.74 80 ;
        RECT 11.46 43.5 12.96 80 ;
        RECT 11.46 0 12.96 38.51 ;
        RECT 5.9 32.55 11.125 44.29 ;
        RECT 8.68 0 10.18 80 ;
        RECT 5.9 0 7.4 80 ;
    END
  END VSS
  OBS
    LAYER metal10 SPACING 0.4 ;
      RECT 0 0 55 80 ;
    LAYER via9 ;
      RECT 0 0 55 80 ;
    LAYER metal9 ;
      RECT 2.67 0 52.33 2 ;
      RECT 0 74.22 55 78.86 ;
      RECT 0 68.3 55 73.62 ;
      RECT 0 43.75 55 50.25 ;
      RECT 0 43.75 3 59.34 ;
      RECT 7.625 43.75 8.615 59.34 ;
      RECT 14.085 43.75 15.075 59.34 ;
      RECT 20.545 43.75 21.535 59.34 ;
      RECT 27.005 43.75 27.995 59.34 ;
      RECT 33.465 43.75 34.455 59.34 ;
      RECT 39.925 43.75 40.915 59.34 ;
      RECT 46.385 43.75 47.375 59.34 ;
      RECT 52 43.75 55 59.34 ;
      RECT 0 52.84 55 59.34 ;
      RECT 0 41.43 55 42.95 ;
      RECT 0 39.11 55 40.63 ;
      RECT 0 30.755 55 31.655 ;
      RECT 0 3.5 55 10.5 ;
      RECT 0 12.5 55 20.46 ;
      RECT 0 3.5 3 29.46 ;
      RECT 7.525 3.5 9.195 29.46 ;
      RECT 13.905 3.5 15.575 29.46 ;
      RECT 20.285 3.5 21.955 29.46 ;
      RECT 26.665 3.5 28.335 29.46 ;
      RECT 33.045 3.5 34.715 29.46 ;
      RECT 39.425 3.5 41.095 29.46 ;
      RECT 45.805 3.5 47.475 29.46 ;
      RECT 52 3.5 55 29.46 ;
      RECT 0 22.46 55 29.46 ;
    LAYER metal9 SPACING 0.4 ;
      RECT 0 0 55 80 ;
    LAYER via8 ;
      RECT 0 0 55 80 ;
    LAYER metal8 ;
      RECT 2.67 0 52.33 2 ;
      RECT 0 74.22 55 78.86 ;
      RECT 0 66.87 55 73.62 ;
      RECT 0 61.57 55 65.87 ;
      RECT 0 60.29 55 60.97 ;
      RECT 0 43.75 55 50.25 ;
      RECT 0 43.75 3 59.34 ;
      RECT 7.625 43.75 8.615 59.34 ;
      RECT 14.085 43.75 15.075 59.34 ;
      RECT 20.545 43.75 21.535 59.34 ;
      RECT 27.005 43.75 27.995 59.34 ;
      RECT 33.465 43.75 34.455 59.34 ;
      RECT 39.925 43.75 40.915 59.34 ;
      RECT 46.385 43.75 47.375 59.34 ;
      RECT 52 43.75 55 59.34 ;
      RECT 0 52.84 55 59.34 ;
      RECT 0 41.43 55 42.95 ;
      RECT 0 39.11 55 40.63 ;
      RECT 0 30.755 55 31.655 ;
      RECT 0 3.5 55 10.5 ;
      RECT 0 12.5 55 20.46 ;
      RECT 0 3.5 3 29.46 ;
      RECT 7.525 3.5 9.195 29.46 ;
      RECT 13.905 3.5 15.575 29.46 ;
      RECT 20.285 3.5 21.955 29.46 ;
      RECT 26.665 3.5 28.335 29.46 ;
      RECT 33.045 3.5 34.715 29.46 ;
      RECT 39.425 3.5 41.095 29.46 ;
      RECT 45.805 3.5 47.475 29.46 ;
      RECT 52 3.5 55 29.46 ;
      RECT 0 22.46 55 29.46 ;
    LAYER metal8 SPACING 0.1 ;
      RECT 0 0 55 80 ;
    LAYER via7 ;
      RECT 0 0 55 80 ;
    LAYER metal7 ;
      RECT 2.67 0 52.33 2 ;
      RECT 0 74.22 55 78.86 ;
      RECT 0 66.87 55 73.62 ;
      RECT 0 61.57 55 65.87 ;
      RECT 0 60.29 55 60.97 ;
      RECT 0 43.75 55 50.25 ;
      RECT 0 43.75 3 59.34 ;
      RECT 7.625 43.75 8.615 59.34 ;
      RECT 14.085 43.75 15.075 59.34 ;
      RECT 20.545 43.75 21.535 59.34 ;
      RECT 27.005 43.75 27.995 59.34 ;
      RECT 33.465 43.75 34.455 59.34 ;
      RECT 39.925 43.75 40.915 59.34 ;
      RECT 46.385 43.75 47.375 59.34 ;
      RECT 52 43.75 55 59.34 ;
      RECT 0 52.84 55 59.34 ;
      RECT 0 41.43 55 42.95 ;
      RECT 0 39.11 55 40.63 ;
      RECT 0 30.755 55 31.655 ;
      RECT 0 3.5 55 10.5 ;
      RECT 0 12.5 55 20.46 ;
      RECT 0 3.5 3 29.46 ;
      RECT 7.525 3.5 9.195 29.46 ;
      RECT 13.905 3.5 15.575 29.46 ;
      RECT 20.285 3.5 21.955 29.46 ;
      RECT 26.665 3.5 28.335 29.46 ;
      RECT 33.045 3.5 34.715 29.46 ;
      RECT 39.425 3.5 41.095 29.46 ;
      RECT 45.805 3.5 47.475 29.46 ;
      RECT 52 3.5 55 29.46 ;
      RECT 0 22.46 55 29.46 ;
    LAYER metal7 SPACING 0.1 ;
      RECT 0 0 55 80 ;
    LAYER via6 ;
      RECT 0 0 55 80 ;
    LAYER metal6 ;
      RECT 2.67 0 52.33 2 ;
      RECT 0 74.22 55 78.86 ;
      RECT 0 66.87 55 73.62 ;
      RECT 0 61.57 55 65.87 ;
      RECT 0 60.29 55 60.97 ;
      RECT 0 43.75 55 50.25 ;
      RECT 0 43.75 3 59.34 ;
      RECT 7.625 43.75 8.615 59.34 ;
      RECT 14.085 43.75 15.075 59.34 ;
      RECT 20.545 43.75 21.535 59.34 ;
      RECT 27.005 43.75 27.995 59.34 ;
      RECT 33.465 43.75 34.455 59.34 ;
      RECT 39.925 43.75 40.915 59.34 ;
      RECT 46.385 43.75 47.375 59.34 ;
      RECT 52 43.75 55 59.34 ;
      RECT 0 52.84 55 59.34 ;
      RECT 0 41.43 55 42.95 ;
      RECT 0 39.11 55 40.63 ;
      RECT 0 30.755 55 31.655 ;
      RECT 0 3.5 55 10.5 ;
      RECT 0 12.5 55 20.46 ;
      RECT 0 3.5 3 29.46 ;
      RECT 7.525 3.5 9.195 29.46 ;
      RECT 13.905 3.5 15.575 29.46 ;
      RECT 20.285 3.5 21.955 29.46 ;
      RECT 26.665 3.5 28.335 29.46 ;
      RECT 33.045 3.5 34.715 29.46 ;
      RECT 39.425 3.5 41.095 29.46 ;
      RECT 45.805 3.5 47.475 29.46 ;
      RECT 52 3.5 55 29.46 ;
      RECT 0 22.46 55 29.46 ;
    LAYER metal6 SPACING 0.1 ;
      RECT 0 0 55 80 ;
    LAYER via5 ;
      RECT 0 0 55 80 ;
    LAYER metal5 ;
      RECT 2.67 0 52.33 2 ;
      RECT 0 74.22 55 78.86 ;
      RECT 0 66.87 55 73.62 ;
      RECT 0 61.57 55 65.87 ;
      RECT 0 60.29 55 60.97 ;
      RECT 0 43.75 55 50.25 ;
      RECT 0 43.75 3 59.34 ;
      RECT 7.625 43.75 8.615 59.34 ;
      RECT 14.085 43.75 15.075 59.34 ;
      RECT 20.545 43.75 21.535 59.34 ;
      RECT 27.005 43.75 27.995 59.34 ;
      RECT 33.465 43.75 34.455 59.34 ;
      RECT 39.925 43.75 40.915 59.34 ;
      RECT 46.385 43.75 47.375 59.34 ;
      RECT 52 43.75 55 59.34 ;
      RECT 0 52.84 55 59.34 ;
      RECT 0 41.43 55 42.95 ;
      RECT 0 39.11 55 40.63 ;
      RECT 0 30.755 55 31.655 ;
      RECT 0 3.5 55 10.5 ;
      RECT 0 12.5 55 20.46 ;
      RECT 0 3.5 3 29.46 ;
      RECT 7.525 3.5 9.195 29.46 ;
      RECT 13.905 3.5 15.575 29.46 ;
      RECT 20.285 3.5 21.955 29.46 ;
      RECT 26.665 3.5 28.335 29.46 ;
      RECT 33.045 3.5 34.715 29.46 ;
      RECT 39.425 3.5 41.095 29.46 ;
      RECT 45.805 3.5 47.475 29.46 ;
      RECT 52 3.5 55 29.46 ;
      RECT 0 22.46 55 29.46 ;
    LAYER metal5 SPACING 0.1 ;
      RECT 0 0 55 80 ;
    LAYER via4 ;
      RECT 0 0 55 80 ;
    LAYER metal4 ;
      RECT 2.67 0 52.33 2 ;
      RECT 0 74.22 55 78.86 ;
      RECT 0 66.87 55 73.62 ;
      RECT 0 61.57 55 65.87 ;
      RECT 0 60.29 55 60.97 ;
      RECT 0 43.75 55 50.25 ;
      RECT 0 43.75 3 59.34 ;
      RECT 7.625 43.75 8.615 59.34 ;
      RECT 14.085 43.75 15.075 59.34 ;
      RECT 20.545 43.75 21.535 59.34 ;
      RECT 27.005 43.75 27.995 59.34 ;
      RECT 33.465 43.75 34.455 59.34 ;
      RECT 39.925 43.75 40.915 59.34 ;
      RECT 46.385 43.75 47.375 59.34 ;
      RECT 52 43.75 55 59.34 ;
      RECT 0 52.84 55 59.34 ;
      RECT 0 41.43 55 42.95 ;
      RECT 0 39.11 55 40.63 ;
      RECT 0 30.755 55 31.655 ;
      RECT 0 3.5 55 10.5 ;
      RECT 0 12.5 55 20.46 ;
      RECT 0 3.5 3 29.46 ;
      RECT 7.525 3.5 9.195 29.46 ;
      RECT 13.905 3.5 15.575 29.46 ;
      RECT 20.285 3.5 21.955 29.46 ;
      RECT 26.665 3.5 28.335 29.46 ;
      RECT 33.045 3.5 34.715 29.46 ;
      RECT 39.425 3.5 41.095 29.46 ;
      RECT 45.805 3.5 47.475 29.46 ;
      RECT 52 3.5 55 29.46 ;
      RECT 0 22.46 55 29.46 ;
    LAYER metal4 SPACING 0.1 ;
      RECT 0 0 55 80 ;
    LAYER via3 ;
      RECT 0 0 55 80 ;
    LAYER metal3 ;
      RECT 0 61.57 3.425 65.87 ;
      RECT 0 66.87 4.33 73.62 ;
      RECT 0.6 41.43 5.4 42.95 ;
      RECT 0.6 39.11 5.4 40.63 ;
      RECT 0 74.22 5.69 75.72 ;
      RECT 0 74.22 0.5 78.86 ;
      RECT 4.83 61.57 5.69 78.86 ;
      RECT 0 77.36 5.69 78.86 ;
      RECT 4.83 44.5 5.69 59.34 ;
      RECT 4.83 3 5.69 31.92 ;
      RECT 7.61 61.57 8.47 78.86 ;
      RECT 7.61 60.29 8.47 60.97 ;
      RECT 7.61 44.5 8.47 59.34 ;
      RECT 7.61 3 8.47 31.92 ;
      RECT 10.39 61.57 11.25 78.86 ;
      RECT 10.39 60.29 11.25 60.97 ;
      RECT 10.39 44.5 11.25 59.34 ;
      RECT 10.39 3 11.25 31.92 ;
      RECT 11.625 41.43 12.065 42.95 ;
      RECT 11.625 39.11 12.065 40.63 ;
      RECT 13.17 61.57 14.03 78.86 ;
      RECT 13.17 60.29 14.03 60.97 ;
      RECT 13.17 44.5 14.03 59.34 ;
      RECT 13.17 3 14.03 31.92 ;
      RECT 15.95 61.57 16.81 78.86 ;
      RECT 15.95 60.29 16.81 60.97 ;
      RECT 15.95 44.5 16.81 59.34 ;
      RECT 15.95 3 16.81 31.92 ;
      RECT 18.73 61.57 19.59 78.86 ;
      RECT 18.73 60.29 19.59 60.97 ;
      RECT 18.73 44.5 19.59 59.34 ;
      RECT 18.73 3 19.59 31.92 ;
      RECT 21.51 61.57 22.37 78.86 ;
      RECT 21.51 60.29 22.37 60.97 ;
      RECT 21.51 44.5 22.37 59.34 ;
      RECT 21.51 3 22.37 31.92 ;
      RECT 22.06 41.43 22.5 42.95 ;
      RECT 22.06 39.11 22.5 40.63 ;
      RECT 24.29 61.57 25.15 78.86 ;
      RECT 24.29 60.29 25.15 60.97 ;
      RECT 24.29 44.5 25.15 59.34 ;
      RECT 24.29 3 25.15 31.92 ;
      RECT 27.07 61.57 27.93 78.86 ;
      RECT 27.07 60.29 27.93 60.97 ;
      RECT 27.07 44.5 27.93 59.34 ;
      RECT 27.07 3 27.93 31.92 ;
      RECT 29.85 61.57 30.71 78.86 ;
      RECT 29.85 60.29 30.71 60.97 ;
      RECT 29.85 44.5 30.71 59.34 ;
      RECT 29.85 3 30.71 31.92 ;
      RECT 32.495 41.43 32.935 42.95 ;
      RECT 32.495 39.11 32.935 40.63 ;
      RECT 32.63 61.57 33.49 78.86 ;
      RECT 32.63 60.29 33.49 60.97 ;
      RECT 32.63 44.5 33.49 59.34 ;
      RECT 32.63 3 33.49 31.92 ;
      RECT 35.41 61.57 36.27 78.86 ;
      RECT 35.41 60.29 36.27 60.97 ;
      RECT 35.41 44.5 36.27 59.34 ;
      RECT 35.41 3 36.27 31.92 ;
      RECT 38.19 61.57 39.05 78.86 ;
      RECT 38.19 60.29 39.05 60.97 ;
      RECT 38.19 44.5 39.05 59.34 ;
      RECT 38.19 3 39.05 31.92 ;
      RECT 40.97 61.57 41.83 78.86 ;
      RECT 40.97 60.29 41.83 60.97 ;
      RECT 40.97 44.5 41.83 59.34 ;
      RECT 40.97 3 41.83 31.92 ;
      RECT 42.93 41.43 43.37 42.95 ;
      RECT 42.93 39.11 43.37 40.63 ;
      RECT 43.75 61.57 44.61 78.86 ;
      RECT 43.75 60.29 44.61 60.97 ;
      RECT 43.75 44.5 44.61 59.34 ;
      RECT 43.75 3 44.61 31.92 ;
      RECT 46.53 61.57 47.39 78.86 ;
      RECT 46.53 60.29 47.39 60.97 ;
      RECT 46.53 44.5 47.39 59.34 ;
      RECT 46.53 3 47.39 31.92 ;
      RECT 49.31 44.5 50.17 59.34 ;
      RECT 49.31 3 50.17 31.92 ;
      RECT 49.6 41.43 54.4 42.95 ;
      RECT 49.6 39.11 54.4 40.63 ;
      RECT 49.31 74.22 55 75.72 ;
      RECT 49.31 61.57 50.17 78.86 ;
      RECT 54.5 74.22 55 78.86 ;
      RECT 49.31 77.36 55 78.86 ;
      RECT 50.67 66.87 55 73.62 ;
      RECT 51.575 61.57 55 65.87 ;
    LAYER metal3 SPACING 0.1 ;
      RECT 0 0 2.495 80 ;
      RECT 0 2.175 5.725 80 ;
      RECT 7.575 44.465 8.505 79.025 ;
      RECT 7.575 2.175 8.505 32.375 ;
      RECT 10.355 44.465 11.285 79.025 ;
      RECT 10.355 2.175 11.285 32.375 ;
      RECT 11.3 38.685 12.39 43.325 ;
      RECT 13.135 44.465 14.065 79.025 ;
      RECT 13.135 2.175 14.065 32.375 ;
      RECT 15.915 44.465 16.845 79.025 ;
      RECT 15.915 2.175 16.845 32.375 ;
      RECT 18.695 44.465 19.625 79.025 ;
      RECT 18.695 2.175 19.625 32.375 ;
      RECT 21.475 44.465 22.405 79.025 ;
      RECT 21.475 2.175 22.405 32.375 ;
      RECT 21.735 38.685 22.825 43.325 ;
      RECT 24.255 44.465 25.185 79.025 ;
      RECT 24.255 2.175 25.185 32.375 ;
      RECT 27.035 44.465 27.965 79.025 ;
      RECT 27.035 2.175 27.965 32.375 ;
      RECT 29.815 44.465 30.745 79.025 ;
      RECT 29.815 2.175 30.745 32.375 ;
      RECT 32.17 38.685 33.26 43.325 ;
      RECT 32.595 44.465 33.525 79.025 ;
      RECT 32.595 2.175 33.525 32.375 ;
      RECT 35.375 44.465 36.305 79.025 ;
      RECT 35.375 2.175 36.305 32.375 ;
      RECT 38.155 44.465 39.085 79.025 ;
      RECT 38.155 2.175 39.085 32.375 ;
      RECT 40.935 44.465 41.865 79.025 ;
      RECT 40.935 2.175 41.865 32.375 ;
      RECT 42.605 38.67 43.695 43.325 ;
      RECT 43.715 44.465 44.645 79.025 ;
      RECT 43.715 2.175 44.645 32.375 ;
      RECT 46.495 44.465 47.425 79.025 ;
      RECT 46.495 2.175 47.425 32.375 ;
      RECT 52.505 0 55 80 ;
      RECT 49.275 2.175 55 80 ;
    LAYER via2 ;
      RECT 0 0 55 80 ;
    LAYER metal2 ;
      RECT 0 61.57 3.425 63.07 ;
      RECT 0 61.57 0.5 65.87 ;
      RECT 0 64.37 3.425 65.87 ;
      RECT 0 66.87 4.33 73.62 ;
      RECT 0.6 41.43 5.4 42.95 ;
      RECT 0.6 39.11 5.4 40.63 ;
      RECT 0 74.22 5.69 75.72 ;
      RECT 0 74.22 0.5 78.86 ;
      RECT 4.83 61.57 5.69 78.86 ;
      RECT 0 77.36 5.69 78.86 ;
      RECT 4.83 44.5 5.69 59.34 ;
      RECT 4.83 3 5.69 31.92 ;
      RECT 7.61 61.57 8.47 78.86 ;
      RECT 7.61 60.29 8.47 60.97 ;
      RECT 7.61 44.5 8.47 59.34 ;
      RECT 7.61 3 8.47 31.92 ;
      RECT 10.39 61.57 11.25 78.86 ;
      RECT 10.39 60.29 11.25 60.97 ;
      RECT 10.39 44.5 11.25 59.34 ;
      RECT 10.39 3 11.25 31.92 ;
      RECT 11.625 41.43 12.065 42.95 ;
      RECT 11.625 39.11 12.065 40.63 ;
      RECT 13.17 61.57 14.03 78.86 ;
      RECT 13.17 60.29 14.03 60.97 ;
      RECT 13.17 44.5 14.03 59.34 ;
      RECT 13.17 3 14.03 31.92 ;
      RECT 15.95 61.57 16.81 78.86 ;
      RECT 15.95 60.29 16.81 60.97 ;
      RECT 15.95 44.5 16.81 59.34 ;
      RECT 15.95 3 16.81 31.92 ;
      RECT 18.73 61.57 19.59 78.86 ;
      RECT 18.73 60.29 19.59 60.97 ;
      RECT 18.73 44.5 19.59 59.34 ;
      RECT 18.73 3 19.59 31.92 ;
      RECT 21.51 61.57 22.37 78.86 ;
      RECT 21.51 60.29 22.37 60.97 ;
      RECT 21.51 44.5 22.37 59.34 ;
      RECT 21.51 3 22.37 31.92 ;
      RECT 22.06 41.43 22.5 42.95 ;
      RECT 22.06 39.11 22.5 40.63 ;
      RECT 24.29 61.57 25.15 78.86 ;
      RECT 24.29 60.29 25.15 60.97 ;
      RECT 24.29 44.5 25.15 59.34 ;
      RECT 24.29 3 25.15 31.92 ;
      RECT 27.07 61.57 27.93 78.86 ;
      RECT 27.07 60.29 27.93 60.97 ;
      RECT 27.07 44.5 27.93 59.34 ;
      RECT 27.07 3 27.93 31.92 ;
      RECT 29.85 61.57 30.71 78.86 ;
      RECT 29.85 60.29 30.71 60.97 ;
      RECT 29.85 44.5 30.71 59.34 ;
      RECT 29.85 3 30.71 31.92 ;
      RECT 32.495 41.43 32.935 42.95 ;
      RECT 32.495 39.11 32.935 40.63 ;
      RECT 32.63 61.57 33.49 78.86 ;
      RECT 32.63 60.29 33.49 60.97 ;
      RECT 32.63 44.5 33.49 59.34 ;
      RECT 32.63 3 33.49 31.92 ;
      RECT 35.41 61.57 36.27 78.86 ;
      RECT 35.41 60.29 36.27 60.97 ;
      RECT 35.41 44.5 36.27 59.34 ;
      RECT 35.41 3 36.27 31.92 ;
      RECT 38.19 61.57 39.05 78.86 ;
      RECT 38.19 60.29 39.05 60.97 ;
      RECT 38.19 44.5 39.05 59.34 ;
      RECT 38.19 3 39.05 31.92 ;
      RECT 40.97 61.57 41.83 78.86 ;
      RECT 40.97 60.29 41.83 60.97 ;
      RECT 40.97 44.5 41.83 59.34 ;
      RECT 40.97 3 41.83 31.92 ;
      RECT 42.93 41.43 43.37 42.95 ;
      RECT 42.93 39.11 43.37 40.63 ;
      RECT 43.75 61.57 44.61 78.86 ;
      RECT 43.75 60.29 44.61 60.97 ;
      RECT 43.75 44.5 44.61 59.34 ;
      RECT 43.75 3 44.61 31.92 ;
      RECT 46.53 61.57 47.39 78.86 ;
      RECT 46.53 60.29 47.39 60.97 ;
      RECT 46.53 44.5 47.39 59.34 ;
      RECT 46.53 3 47.39 31.92 ;
      RECT 49.31 44.5 50.17 59.34 ;
      RECT 49.31 3 50.17 31.92 ;
      RECT 49.6 41.43 54.4 42.95 ;
      RECT 49.6 39.11 54.4 40.63 ;
      RECT 49.31 74.22 55 75.72 ;
      RECT 49.31 61.57 50.17 78.86 ;
      RECT 54.5 74.22 55 78.86 ;
      RECT 49.31 77.36 55 78.86 ;
      RECT 50.67 66.87 55 73.62 ;
      RECT 51.575 61.57 55 63.07 ;
      RECT 54.5 61.57 55 65.87 ;
      RECT 51.575 64.37 55 65.87 ;
    LAYER metal2 SPACING 0.1 ;
      RECT 0 0 2.495 80 ;
      RECT 0 2.175 5.725 80 ;
      RECT 7.575 44.465 8.505 79.025 ;
      RECT 7.575 2.175 8.505 32.375 ;
      RECT 10.355 44.465 11.285 79.025 ;
      RECT 10.355 2.175 11.285 32.375 ;
      RECT 11.3 38.685 12.39 43.325 ;
      RECT 13.135 44.465 14.065 79.025 ;
      RECT 13.135 2.175 14.065 32.375 ;
      RECT 15.915 44.465 16.845 79.025 ;
      RECT 15.915 2.175 16.845 32.375 ;
      RECT 18.695 44.465 19.625 79.025 ;
      RECT 18.695 2.175 19.625 32.375 ;
      RECT 21.475 44.465 22.405 79.025 ;
      RECT 21.475 2.175 22.405 32.375 ;
      RECT 21.735 38.685 22.825 43.325 ;
      RECT 24.255 44.465 25.185 79.025 ;
      RECT 24.255 2.175 25.185 32.375 ;
      RECT 27.035 44.465 27.965 79.025 ;
      RECT 27.035 2.175 27.965 32.375 ;
      RECT 29.815 44.465 30.745 79.025 ;
      RECT 29.815 2.175 30.745 32.375 ;
      RECT 32.17 38.685 33.26 43.325 ;
      RECT 32.595 44.465 33.525 79.025 ;
      RECT 32.595 2.175 33.525 32.375 ;
      RECT 35.375 44.465 36.305 79.025 ;
      RECT 35.375 2.175 36.305 32.375 ;
      RECT 38.155 44.465 39.085 79.025 ;
      RECT 38.155 2.175 39.085 32.375 ;
      RECT 40.935 44.465 41.865 79.025 ;
      RECT 40.935 2.175 41.865 32.375 ;
      RECT 42.605 38.67 43.695 43.325 ;
      RECT 43.715 44.465 44.645 79.025 ;
      RECT 43.715 2.175 44.645 32.375 ;
      RECT 46.495 44.465 47.425 79.025 ;
      RECT 46.495 2.175 47.425 32.375 ;
      RECT 52.505 0 55 80 ;
      RECT 49.275 2.175 55 80 ;
    LAYER via1 ;
      RECT 0 0 55 80 ;
    LAYER metal1 ;
      RECT 0 61.57 3.425 61.97 ;
      RECT 0 61.57 0.5 65.87 ;
      RECT 1.275 61.57 1.525 65.87 ;
      RECT 2.225 61.57 2.475 65.87 ;
      RECT 3.175 61.57 3.425 65.87 ;
      RECT 0 65.47 3.425 65.87 ;
      RECT 0 66.87 4.33 67.27 ;
      RECT 1.5 66.87 1.9 67.775 ;
      RECT 2.7 66.87 3.1 67.775 ;
      RECT 0 66.87 0.5 73.62 ;
      RECT 1.5 72.85 1.9 73.62 ;
      RECT 2.7 72.85 3.1 73.62 ;
      RECT 3.83 66.87 4.33 73.62 ;
      RECT 0 73.22 4.33 73.62 ;
      RECT 0 60.29 5.165 60.97 ;
      RECT 0 41.43 5.4 42.95 ;
      RECT 0 39.11 5.4 40.63 ;
      RECT 0 74.22 5.69 74.62 ;
      RECT 0 74.22 0.5 78.86 ;
      RECT 1.25 74.22 1.5 78.86 ;
      RECT 2.2 74.22 2.45 78.86 ;
      RECT 3.15 74.22 3.4 78.86 ;
      RECT 4.1 74.22 4.35 78.86 ;
      RECT 4.83 61.57 5.69 78.86 ;
      RECT 0 78.5 5.69 78.86 ;
      RECT 0 43.75 5.69 45.08 ;
      RECT 0 43.75 0.5 59.34 ;
      RECT 3.185 43.75 5.69 59.34 ;
      RECT 0 57.81 5.69 59.34 ;
      RECT 7.61 61.57 8.47 78.86 ;
      RECT 7.61 60.29 8.47 60.97 ;
      RECT 7.61 44.5 8.47 59.34 ;
      RECT 10.39 61.57 11.25 78.86 ;
      RECT 10.39 60.29 11.25 60.97 ;
      RECT 10.39 44.5 11.25 59.34 ;
      RECT 11.625 41.43 12.065 42.95 ;
      RECT 11.625 39.11 12.065 40.63 ;
      RECT 13.17 61.57 14.03 78.86 ;
      RECT 13.17 60.29 14.03 60.97 ;
      RECT 13.17 44.5 14.03 59.34 ;
      RECT 15.95 61.57 16.81 78.86 ;
      RECT 15.95 60.29 16.81 60.97 ;
      RECT 15.95 44.5 16.81 59.34 ;
      RECT 18.73 61.57 19.59 78.86 ;
      RECT 18.73 60.29 19.59 60.97 ;
      RECT 18.73 44.5 19.59 59.34 ;
      RECT 21.51 61.57 22.37 78.86 ;
      RECT 21.51 60.29 22.37 60.97 ;
      RECT 21.51 44.5 22.37 59.34 ;
      RECT 22.06 41.43 22.5 42.95 ;
      RECT 22.06 39.11 22.5 40.63 ;
      RECT 24.29 61.57 25.15 78.86 ;
      RECT 24.29 60.29 25.15 60.97 ;
      RECT 24.29 44.5 25.15 59.34 ;
      RECT 27.07 61.57 27.93 78.86 ;
      RECT 27.07 60.29 27.93 60.97 ;
      RECT 27.07 44.5 27.93 59.34 ;
      RECT 29.85 61.57 30.71 78.86 ;
      RECT 29.85 60.29 30.71 60.97 ;
      RECT 29.85 44.5 30.71 59.34 ;
      RECT 32.495 41.43 32.935 42.95 ;
      RECT 32.495 39.11 32.935 40.63 ;
      RECT 32.63 61.57 33.49 78.86 ;
      RECT 32.63 60.29 33.49 60.97 ;
      RECT 32.63 44.5 33.49 59.34 ;
      RECT 35.41 61.57 36.27 78.86 ;
      RECT 35.41 60.29 36.27 60.97 ;
      RECT 35.41 44.5 36.27 59.34 ;
      RECT 38.19 61.57 39.05 78.86 ;
      RECT 38.19 60.29 39.05 60.97 ;
      RECT 38.19 44.5 39.05 59.34 ;
      RECT 40.97 61.57 41.83 78.86 ;
      RECT 40.97 60.29 41.83 60.97 ;
      RECT 40.97 44.5 41.83 59.34 ;
      RECT 42.93 41.43 43.37 42.95 ;
      RECT 42.93 39.11 43.37 40.63 ;
      RECT 43.75 61.57 44.61 78.86 ;
      RECT 43.75 60.29 44.61 60.97 ;
      RECT 43.75 44.5 44.61 59.34 ;
      RECT 46.53 61.57 47.39 78.86 ;
      RECT 46.53 60.29 47.39 60.97 ;
      RECT 46.53 44.5 47.39 59.34 ;
      RECT 49.31 74.22 55 74.62 ;
      RECT 49.31 61.57 50.17 78.86 ;
      RECT 50.65 74.22 50.9 78.86 ;
      RECT 51.6 74.22 51.85 78.86 ;
      RECT 52.55 74.22 52.8 78.86 ;
      RECT 53.5 74.22 53.75 78.86 ;
      RECT 54.5 74.22 55 78.86 ;
      RECT 49.31 78.5 55 78.86 ;
      RECT 50.67 66.87 55 67.27 ;
      RECT 51.9 66.87 52.3 67.775 ;
      RECT 53.1 66.87 53.5 67.775 ;
      RECT 50.67 66.87 51.17 73.62 ;
      RECT 51.9 72.85 52.3 73.62 ;
      RECT 53.1 72.85 53.5 73.62 ;
      RECT 54.5 66.87 55 73.62 ;
      RECT 50.67 73.22 55 73.62 ;
      RECT 51.575 61.57 55 61.97 ;
      RECT 51.575 61.57 51.825 65.87 ;
      RECT 52.525 61.57 52.775 65.87 ;
      RECT 53.475 61.57 53.725 65.87 ;
      RECT 54.5 61.57 55 65.87 ;
      RECT 51.575 65.47 55 65.87 ;
      RECT 49.875 60.29 55 60.97 ;
      RECT 49.31 43.75 55 45.08 ;
      RECT 49.31 43.75 51.815 59.34 ;
      RECT 54.5 43.75 55 59.34 ;
      RECT 49.31 57.81 55 59.34 ;
      RECT 49.6 41.43 55 42.95 ;
      RECT 49.6 39.11 55 40.63 ;
      RECT 0 0 55 1.03 ;
      RECT 0 0 5.69 1.56 ;
      RECT 49.31 0 55 1.56 ;
      RECT 0 0 0.5 38.31 ;
      RECT 7.61 0 8.47 31.92 ;
      RECT 10.39 0 11.25 31.92 ;
      RECT 13.17 0 14.03 31.92 ;
      RECT 15.95 0 16.81 31.92 ;
      RECT 18.73 0 19.59 31.92 ;
      RECT 21.51 0 22.37 31.92 ;
      RECT 24.29 0 25.15 31.92 ;
      RECT 27.07 0 27.93 31.92 ;
      RECT 29.85 0 30.71 31.92 ;
      RECT 32.63 0 33.49 31.92 ;
      RECT 35.41 0 36.27 31.92 ;
      RECT 38.19 0 39.05 31.92 ;
      RECT 40.97 0 41.83 31.92 ;
      RECT 43.75 0 44.61 31.92 ;
      RECT 46.53 0 47.39 31.92 ;
      RECT 3.83 0 5.69 31.96 ;
      RECT 49.31 0 51.17 31.97 ;
      RECT 0 31.87 5.65 32.01 ;
      RECT 49.36 31.87 55 32.02 ;
      RECT 0 31.87 5.6 32.06 ;
      RECT 49.41 31.87 55 32.07 ;
      RECT 0 31.87 5.55 32.11 ;
      RECT 49.46 31.87 55 32.12 ;
      RECT 0 31.87 5.5 32.16 ;
      RECT 49.51 31.87 55 32.17 ;
      RECT 0 31.87 5.45 32.21 ;
      RECT 49.56 31.87 55 32.21 ;
      RECT 0 31.87 5.4 38.31 ;
      RECT 54.5 0 55 38.31 ;
      RECT 49.6 31.87 55 38.31 ;
    LAYER metal1 SPACING 0.09 ;
      RECT 7.565 44.455 8.515 79.035 ;
      RECT 10.345 44.455 11.295 79.035 ;
      RECT 11.29 38.675 12.4 43.335 ;
      RECT 13.125 44.455 14.075 79.035 ;
      RECT 15.905 44.455 16.855 79.035 ;
      RECT 18.685 44.455 19.635 79.035 ;
      RECT 21.465 44.455 22.415 79.035 ;
      RECT 21.725 38.675 22.835 43.335 ;
      RECT 24.245 44.455 25.195 79.035 ;
      RECT 27.025 44.455 27.975 79.035 ;
      RECT 29.805 44.455 30.755 79.035 ;
      RECT 32.16 38.675 33.27 43.335 ;
      RECT 32.585 44.455 33.535 79.035 ;
      RECT 35.365 44.455 36.315 79.035 ;
      RECT 38.145 44.455 39.095 79.035 ;
      RECT 40.925 44.455 41.875 79.035 ;
      RECT 42.595 38.66 43.705 43.335 ;
      RECT 43.705 44.455 44.655 79.035 ;
      RECT 46.485 44.455 47.435 79.035 ;
      RECT 0 0 55 1.065 ;
      RECT 7.565 0 8.515 32.385 ;
      RECT 10.345 0 11.295 32.385 ;
      RECT 13.125 0 14.075 32.385 ;
      RECT 15.905 0 16.855 32.385 ;
      RECT 18.685 0 19.635 32.385 ;
      RECT 21.465 0 22.415 32.385 ;
      RECT 24.245 0 25.195 32.385 ;
      RECT 27.025 0 27.975 32.385 ;
      RECT 29.805 0 30.755 32.385 ;
      RECT 32.585 0 33.535 32.385 ;
      RECT 35.365 0 36.315 32.385 ;
      RECT 38.145 0 39.095 32.385 ;
      RECT 40.925 0 41.875 32.385 ;
      RECT 43.705 0 44.655 32.385 ;
      RECT 46.485 0 47.435 32.385 ;
      RECT 0 0 5.735 80 ;
      RECT 49.265 0 55 80 ;
  END
END GPAD
END LIBRARY
